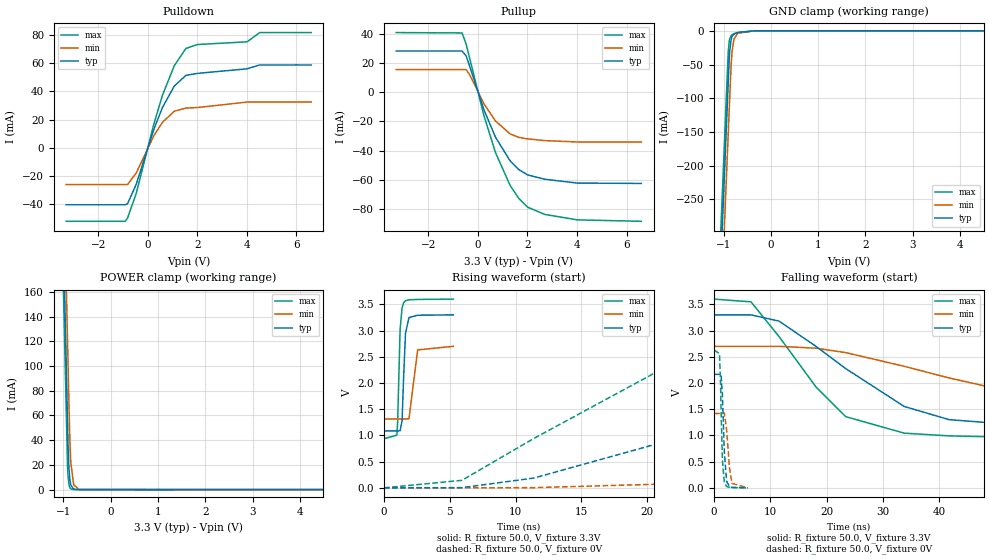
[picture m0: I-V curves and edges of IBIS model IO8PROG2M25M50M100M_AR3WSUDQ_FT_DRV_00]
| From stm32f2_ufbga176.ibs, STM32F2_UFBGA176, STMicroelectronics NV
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| *** New cell (Generated with 5.14beta1 (Sep 20 2010 13:23:23))
[Model]   IO8PROG2M25M50M100M_AR3WSUDQ_FT_DRV_00
Model_type 3-state
Polarity   Non-Inverting
Enable   Active-Low
| CAP_THRESHOLD on pad IOV33 is "CMOS" :
| Rising=10.0% of vddio   Falling=90.0% of vddio
| C_comp min and max val. don't necessarily correlate with the min and max pvt
| but are the smallest and greatest pad capacitance found.
| var   typ   min   max
C_comp   2.51760pF  2.40375pF  2.66060pF
Vmeas = 1.65V   | Reference voltage for timing measurements
Cref  = 50.0pF   | Timing specification test load capacitance value
Rref  = 10.0MOhm   | Timing specification test load resistance value
Vref  = 1.65V   | Timing specification test load voltage
[Model Spec]
| variable   typ   min   max
[Temperature Range] 25.0 125.0 -40.0
| variable   typ   min   max
[Voltage Range] 3.3V 2.7V 3.6V
| variable   typ   min   max
[POWER Clamp Reference] 3.3V 2.7V 3.6V
| variable   typ   min   max
[GND Clamp Reference] 0V 0V 0V
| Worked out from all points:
|   slope of the pulldown table from 0 to 0.495 V, typ, clamps not added: 20 ohm
|   slope of the pullup table from 0 to 0.495 V, typ, clamps not added: 21.7 ohm
|   GND clamp passes 1 mA (typ) near -0.59 V on its own axis
|   POWER clamp passes 1 mA (typ) near -0.81 V on its own axis
|   rising waveform, R_fixture 50.0, V_fixture 3.3V: 20-80 % time 185ps typ, 224ps min, 174ps max; typ from 1.09 V to 3.3 V
|   falling waveform, R_fixture 50.0, V_fixture 3.3V: 20-80 % time 18.1ns typ, 35.5ns min, 11.7ns max; typ from 3.3 V to 1.09 V
|   rising waveform, R_fixture 50.0, V_fixture 0V: 20-80 % time 19.4ns typ, 43.9ns min, 10.8ns max; typ from 0 V to 2.17 V
|   falling waveform, R_fixture 50.0, V_fixture 0V: 20-80 % time 445ps typ, 629ps min, 359ps max; typ from 2.17 V to 0.001 V
[POWER Clamp]
-3.3V     4.117A     4.183A     4.076A
-1.09V    360mA      425.6mA    319.3mA
-1.05V    292mA      357.6mA    251.3mA
-1.01V    224mA      289.6mA    183.3mA
-910mV    53.96mA    119.6mA    18.43mA
-900mV    36.96mA    102.6mA    11.2mA
-880mV    16.97mA    68.61mA    4.141mA
-860mV    7.791mA    38.56mA    1.53mA
-840mV    3.577mA    21.53mA    565.5uA
-780mV    346.2uA    3.745mA    28.55uA
-660mV    3.242uA    113.2uA    73.21nA
6.6V      0A         0A         0A
[GND Clamp]
-3.3V     -4.156A    -4.231A    -4.108A
-1.06V    -347.5mA   -423.2mA   -300.1mA
-940mV    -143.5mA   -219.2mA   -96.09mA
-900mV    -75.54mA   -151.2mA   -30.39mA
-880mV    -41.78mA   -117.2mA   -15.62mA
-870mV    -30.28mA   -100.2mA   -12.04mA
-840mV    -13.1mA    -50.87mA   -7.186mA
-820mV    -8.54mA    -30.65mA   -5.881mA
-780mV    -4.86mA    -12.37mA   -4.416mA
-700mV    -2.552mA   -3.603mA   -2.454mA
-350mV    -11.93uA   -60.06uA   -2.46uA
6.6V      10.25nA    1.32uA     122.8pA
| variable   typ   min   max
[Pullup Reference] 3.3V 2.7V 3.6V
| variable   typ   min   max
[Pulldown Reference] 0V 0V 0V
[Pullup]
-3.3V     28.36mA    15.61mA    40.99mA
-640mV    28.36mA    15.61mA    40.72mA
-480mV    25.12mA    15.61mA    33.23mA
-350mV    18.69mA    12.65mA    24.51mA
240mV     -11.89mA   -7.822mA   -15.87mA
710mV     -30.8mA    -19.68mA   -41.36mA
1.3V      -47.02mA   -28.56mA   -63.9mA
1.65V     -53.05mA   -30.92mA   -72.82mA
2.01V     -56.71mA   -31.98mA   -78.86mA
2.7V      -59.67mA   -33.14mA   -83.8mA
4.01V     -62.27mA   -34.07mA   -87.53mA
6.6V      -62.54mA   -34.07mA   -88.51mA
[Pulldown]
-3.3V     -40.26mA   -25.94mA   -51.99mA
-910mV    -40.26mA   -25.94mA   -51.99mA
-820mV    -39.59mA   -25.94mA   -49.78mA
-470mV    -25.89mA   -17.87mA   -32.39mA
240mV     12.97mA    8.52mA     16.62mA
590mV     28.62mA    18.11mA    37.2mA
1.07V     43.85mA    26mA       58.31mA
1.54V     51.42mA    28.24mA    70.48mA
2.01V     52.82mA    28.63mA    73.27mA
4.01V     56.05mA    32.5mA     75.18mA
4.52V     58.79mA    32.5mA     81.73mA
6.6V      58.79mA    32.5mA     81.73mA
[Ramp]
dV/dt_r 1.29886V/19.41372ns 851.11157mV/43.87102ns 1.57727V/10.7781ns
dV/dt_f 1.3278V/18.13381ns 831.267mV/35.53476ns 1.59819V/11.73814ns
R_load = 50.0
| Removed startup time: 0s 0s 0s  .
| Removed end time: 5.264ns.
[Rising Waveform]
R_fixture   = 50.0
V_fixture   = 3.3V
V_fixture_min = 2.7V
V_fixture_max = 3.6V
0s        1.087V     1.314V     936.3mV
980ps     1.087V     1.314V     1.005V
1.04ns    1.086V     1.314V     1.255V
1.226ns   1.09V      1.314V     3.019V
1.378ns   1.278V     1.314V     3.436V
1.486ns   2.063V     1.314V     3.527V
1.636ns   2.946V     1.312V     3.569V
1.902ns   3.248V     1.319V     3.586V
2.56ns    3.292V     2.631V     3.593V
5.268ns   3.299V     2.699V     3.599V
| Removed startup time: 0s 0s 0s  .
| Removed end time: 250.2ns.
[Falling Waveform]
R_fixture   = 50.0
V_fixture   = 3.3V
V_fixture_min = 2.7V
V_fixture_max = 3.6V
0s        3.3V       2.7V       3.6V
6.56ns    3.3V       2.7V       3.548V
11.56ns   3.18V      2.7V       2.885V
18.16ns   2.696V     2.664V     1.919V
23.4ns    2.275V     2.58V      1.359V
33.8ns    1.553V     2.319V     1.044V
41.76ns   1.302V     2.097V     992mV
58.96ns   1.16V      1.684V     953.1mV
85.32ns   1.107V     1.443V     940mV
250.3ns   1.087V     1.315V     936.3mV
| Removed startup time: 0s 0s 0s  .
| Removed end time: 242.72ns.
[Rising Waveform]
R_fixture   = 50.0
V_fixture   = 0V
V_fixture_min = 0V
V_fixture_max = 0V
0s        8.518nV    394.5nV    5.764nV
5.92ns    3.855mV    -137.4uV   143.5mV
11.4ns    188mV      3.643mV    944.4mV
20.84ns   846.3mV    70.12mV    2.228V
31.12ns   1.546V     245.4mV    2.545V
38.12ns   1.868V     393.2mV    2.594V
48.88ns   2.05V      635.5mV    2.618V
72.4ns    2.143V     1.077V     2.628V
93.8ns    2.159V     1.284V     2.629V
242.8ns   2.165V     1.419V     2.629V
| Removed startup time: 0s 0s 0s  .
| Removed end time: 5.988ns.
[Falling Waveform]
R_fixture   = 50.0
V_fixture   = 0V
V_fixture_min = 0V
V_fixture_max = 0V
0s        2.165V     1.419V     2.629V
960ps     2.166V     1.419V     2.56V
1.14ns    2.172V     1.419V     2.046V
1.272ns   2.134V     1.418V     1.377V
1.484ns   1.754V     1.419V     524.3mV
1.822ns   693mV      1.428V     110.8mV
2.22ns    128.6mV    1.119V     28.35mV
2.734ns   24.13mV    386mV      10.84mV
3.182ns   9.881mV    87.57mV    7.349mV
5.992ns   1.124mV    1.064mV    1.02mV
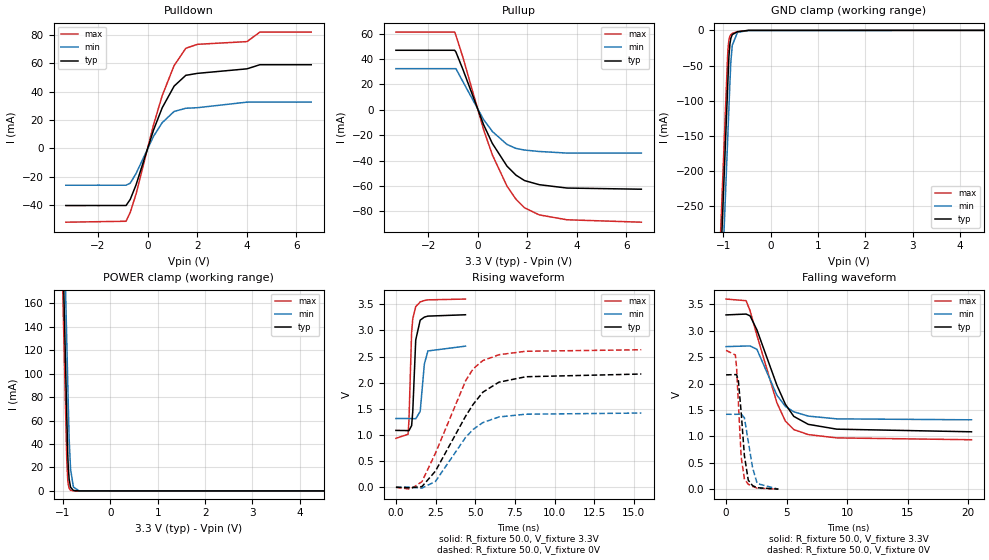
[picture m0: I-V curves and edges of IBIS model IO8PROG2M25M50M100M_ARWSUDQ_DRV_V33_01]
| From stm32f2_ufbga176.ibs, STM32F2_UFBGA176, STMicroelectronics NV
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| *** New cell (Generated with 5.14beta1 (Sep 20 2010 13:23:23))
[Model]   IO8PROG2M25M50M100M_ARWSUDQ_DRV_V33_01
Model_type 3-state
Polarity   Non-Inverting
Enable   Active-Low
| CAP_THRESHOLD on pad IOV33 is "CMOS" :
| Rising=10.0% of vddio   Falling=90.0% of vddio
| C_comp min and max val. don't necessarily correlate with the min and max pvt
| but are the smallest and greatest pad capacitance found.
| var   typ   min   max
C_comp   2.45675pF  2.35635pF  2.58870pF
Vmeas = 1.65V   | Reference voltage for timing measurements
Cref  = 50.0pF   | Timing specification test load capacitance value
Rref  = 1.0MOhm   | Timing specification test load resistance value
Vref  = 1.65V   | Timing specification test load voltage
[Model Spec]
| variable   typ   min   max
[Temperature Range] 25.0 125.0 -40.0
| variable   typ   min   max
[Voltage Range] 3.3V 2.7V 3.6V
| variable   typ   min   max
[POWER Clamp Reference] 3.3V 2.7V 3.6V
| variable   typ   min   max
[GND Clamp Reference] 0V 0V 0V
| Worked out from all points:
|   slope of the pulldown table from 0 to 0.495 V, typ, clamps not added: 20 ohm
|   slope of the pullup table from 0 to 0.495 V, typ, clamps not added: 21.7 ohm
|   GND clamp passes 1 mA (typ) near -0.62 V on its own axis
|   POWER clamp passes 1 mA (typ) near -0.81 V on its own axis
|   rising waveform, R_fixture 50.0, V_fixture 3.3V: 20-80 % time 186ps typ, 233ps min, 172ps max; typ from 1.09 V to 3.3 V
|   falling waveform, R_fixture 50.0, V_fixture 3.3V: 20-80 % time 2.28ns typ, 1.79ns min, 2.12ns max; typ from 3.3 V to 1.09 V
|   rising waveform, R_fixture 50.0, V_fixture 0V: 20-80 % time 2.5ns typ, 2.07ns min, 2.19ns max; typ from 0 V to 2.17 V
|   falling waveform, R_fixture 50.0, V_fixture 0V: 20-80 % time 440ps typ, 624ps min, 354ps max; typ from 2.17 V to 0.001 V
[POWER Clamp]
-3.3V     4.11A      4.173A     4.072A
-1.09V    352.6mA    415.9mA    314.7mA
-1.05V    284.6mA    347.9mA    246.7mA
-1.01V    216.6mA    279.9mA    178.7mA
-920mV    63.6mA     126.9mA    25.98mA
-900mV    31.61mA    92.95mA    9.679mA
-890mV    21.44mA    75.95mA    5.93mA
-870mV    9.888mA    44.06mA    2.262mA
-840mV    3.126mA    18.4mA     586.7uA
-780mV    356.4uA    3.233mA    107.9uA
-660mV    37.87uA    120.8uA    47.09uA
6.6V      0A         0A         0A
[GND Clamp]
-3.3V     -4.149A    -4.224A    -4.103A
-1.06V    -340.8mA   -415.7mA   -294.7mA
-940mV    -136.8mA   -211.7mA   -90.7mA
-910mV    -85.75mA   -160.7mA   -39.7mA
-900mV    -68.75mA   -143.7mA   -26.69mA
-880mV    -36.92mA   -109.7mA   -13.58mA
-860mV    -19.7mA    -75.66mA   -8.314mA
-840mV    -11.43mA   -45.13mA   -6.003mA
-810mV    -6.09mA    -21.34mA   -4.418mA
-700mV    -1.961mA   -2.954mA   -1.882mA
-470mV    -105.5uA   -264uA     -47.31uA
6.6V      9.775nA    1.217uA    66.58pA
| variable   typ   min   max
[Pullup Reference] 3.3V 2.7V 3.6V
| variable   typ   min   max
[Pulldown Reference] 0V 0V 0V
[Pullup]
-3.3V     46.87mA    32.39mA    61.2mA
-930mV    46.87mA    32.39mA    61.2mA
-880mV    45.52mA    32.39mA    58.63mA
-590mV    31.39mA    21.86mA    40.83mA
240mV     -11.89mA   -7.822mA   -15.87mA
590mV     -26.5mA    -17.07mA   -35.52mA
1.18V     -44.36mA   -27.27mA   -60.11mA
1.54V     -51.43mA   -30.39mA   -70.35mA
1.89V     -55.75mA   -31.69mA   -77.18mA
2.48V     -58.98mA   -32.83mA   -82.75mA
3.6V      -61.62mA   -34.07mA   -86.61mA
6.6V      -62.54mA   -34.07mA   -88.51mA
[Pulldown]
-3.3V     -40.26mA   -25.94mA   -51.99mA
-870mV    -40.25mA   -25.94mA   -51.33mA
-700mV    -35.92mA   -24.51mA   -45.06mA
-470mV    -25.89mA   -17.87mA   -32.39mA
240mV     12.97mA    8.52mA     16.62mA
590mV     28.62mA    18.11mA    37.2mA
1.07V     43.85mA    26mA       58.31mA
1.54V     51.42mA    28.24mA    70.48mA
2.01V     52.82mA    28.63mA    73.27mA
4.01V     56.01mA    32.56mA    75.18mA
4.53V     58.9mA     32.56mA    81.88mA
6.6V      58.9mA     32.56mA    81.88mA
[Ramp]
dV/dt_r 1.29886V/2.49642ns 851.30661mV/2.06906ns 1.57728V/2.19388ns
dV/dt_f 1.32782V/2.28321ns 831.60245mV/1.78812ns 1.59819V/2.1203ns
R_load = 50.0
| Removed startup time: 0s 0s 0s  .
| Removed end time: 4.382ns.
[Rising Waveform]
R_fixture   = 50.0
V_fixture   = 3.3V
V_fixture_min = 2.7V
V_fixture_max = 3.6V
0s        1.087V     1.314V     936.3mV
764ps     1.084V     1.314V     1.013V
821ps     1.083V     1.314V     1.272V
989ps     1.178V     1.313V     2.957V
1.061ns   1.445V     1.313V     3.219V
1.248ns   2.816V     1.309V     3.453V
1.53ns    3.195V     1.451V     3.543V
1.792ns   3.253V     2.356V     3.57V
2.014ns   3.272V     2.606V     3.583V
4.384ns   3.298V     2.698V     3.598V
| Removed startup time: 0s 0s 0s  .
| Removed end time: 20.27ns.
[Falling Waveform]
R_fixture   = 50.0
V_fixture   = 3.3V
V_fixture_min = 2.7V
V_fixture_max = 3.6V
0s        3.3V       2.7V       3.6V
1.655ns   3.316V     2.711V     3.569V
1.985ns   3.282V     2.711V     3.38V
2.55ns    3.017V     2.649V     2.914V
4.195ns   1.972V     1.782V     1.64V
4.9ns     1.609V     1.568V     1.289V
5.595ns   1.379V     1.466V     1.129V
6.795ns   1.228V     1.384V     1.034V
9.15ns    1.137V     1.332V     971.7mV
20.28ns   1.087V     1.314V     936.6mV
| Removed startup time: 0s 0s 0s  .
| Removed end time: 15.46ns.
[Rising Waveform]
R_fixture   = 50.0
V_fixture   = 0V
V_fixture_min = 0V
V_fixture_max = 0V
0s        11.88nV    319.5nV    8.559nV
920ps     -7.716mV   80.7uV     -36.12mV
1.64ns    13.22mV    -14.92mV   107.4mV
2.49ns    308.8mV    111.2mV    650.3mV
4.395ns   1.361V     955.3mV    2.037V
4.875ns   1.588V     1.108V     2.267V
5.48ns    1.818V     1.237V     2.422V
6.49ns    2.009V     1.344V     2.534V
8.185ns   2.113V     1.397V     2.6V
15.47ns   2.165V     1.419V     2.629V
| Removed startup time: 0s 0s 0s  .
| Removed end time: 4.313ns.
[Falling Waveform]
R_fixture   = 50.0
V_fixture   = 0V
V_fixture_min = 0V
V_fixture_max = 0V
0s        2.165V     1.419V     2.629V
771ps     2.17V      1.418V     2.542V
874ps     2.166V     1.418V     2.289V
1.017ns   2.057V     1.42V      1.644V
1.248ns   1.462V     1.426V     612.2mV
1.516ns   635.4mV    1.352V     195.7mV
1.838ns   170mV      900.3mV    93.88mV
2.192ns   67.61mV    408.4mV    52.69mV
2.574ns   28.63mV    107.1mV    19.97mV
4.315ns   1.209mV    1.558mV    835.1uV
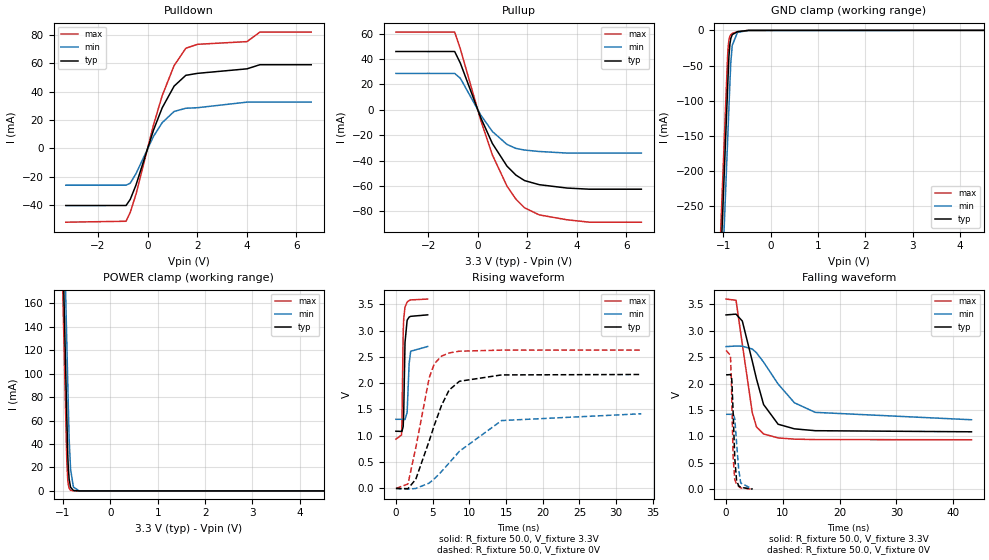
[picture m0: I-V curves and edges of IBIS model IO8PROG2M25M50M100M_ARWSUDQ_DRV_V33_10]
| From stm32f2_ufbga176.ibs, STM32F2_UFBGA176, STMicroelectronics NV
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| *** New cell (Generated with 5.14beta1 (Sep 20 2010 13:23:23))
[Model]   IO8PROG2M25M50M100M_ARWSUDQ_DRV_V33_10
Model_type 3-state
Polarity   Non-Inverting
Enable   Active-Low
| CAP_THRESHOLD on pad IOV33 is "CMOS" :
| Rising=10.0% of vddio   Falling=90.0% of vddio
| C_comp min and max val. don't necessarily correlate with the min and max pvt
| but are the smallest and greatest pad capacitance found.
| var   typ   min   max
C_comp   2.45675pF  2.35635pF  2.58870pF
Vmeas = 1.65V   | Reference voltage for timing measurements
Cref  = 50.0pF   | Timing specification test load capacitance value
Rref  = 1.0MOhm   | Timing specification test load resistance value
Vref  = 1.65V   | Timing specification test load voltage
[Model Spec]
| variable   typ   min   max
[Temperature Range] 25.0 125.0 -40.0
| variable   typ   min   max
[Voltage Range] 3.3V 2.7V 3.6V
| variable   typ   min   max
[POWER Clamp Reference] 3.3V 2.7V 3.6V
| variable   typ   min   max
[GND Clamp Reference] 0V 0V 0V
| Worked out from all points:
|   slope of the pulldown table from 0 to 0.495 V, typ, clamps not added: 20 ohm
|   slope of the pullup table from 0 to 0.495 V, typ, clamps not added: 21.7 ohm
|   GND clamp passes 1 mA (typ) near -0.62 V on its own axis
|   POWER clamp passes 1 mA (typ) near -0.81 V on its own axis
|   rising waveform, R_fixture 50.0, V_fixture 3.3V: 20-80 % time 186ps typ, 231ps min, 172ps max; typ from 1.09 V to 3.3 V
|   falling waveform, R_fixture 50.0, V_fixture 3.3V: 20-80 % time 3.17ns typ, 6.13ns min, 2.08ns max; typ from 3.3 V to 1.09 V
|   rising waveform, R_fixture 50.0, V_fixture 0V: 20-80 % time 3.27ns typ, 6.06ns min, 2.16ns max; typ from 0 V to 2.17 V
|   falling waveform, R_fixture 50.0, V_fixture 0V: 20-80 % time 440ps typ, 624ps min, 354ps max; typ from 2.17 V to 0.001 V
[POWER Clamp]
-3.3V     4.11A      4.173A     4.072A
-1.09V    352.6mA    415.9mA    314.7mA
-1.05V    284.6mA    347.9mA    246.7mA
-1.01V    216.6mA    279.9mA    178.7mA
-920mV    63.6mA     126.9mA    25.98mA
-900mV    31.61mA    92.95mA    9.679mA
-890mV    21.44mA    75.95mA    5.93mA
-870mV    9.888mA    44.06mA    2.262mA
-840mV    3.126mA    18.4mA     586.7uA
-780mV    356.4uA    3.233mA    107.9uA
-660mV    37.87uA    120.8uA    47.09uA
6.6V      0A         0A         0A
[GND Clamp]
-3.3V     -4.149A    -4.224A    -4.103A
-1.06V    -340.8mA   -415.7mA   -294.7mA
-940mV    -136.8mA   -211.7mA   -90.7mA
-910mV    -85.75mA   -160.7mA   -39.7mA
-900mV    -68.75mA   -143.7mA   -26.69mA
-880mV    -36.92mA   -109.7mA   -13.58mA
-860mV    -19.7mA    -75.66mA   -8.314mA
-840mV    -11.43mA   -45.13mA   -6.003mA
-810mV    -6.09mA    -21.34mA   -4.418mA
-700mV    -1.961mA   -2.954mA   -1.882mA
-470mV    -105.5uA   -264uA     -47.31uA
6.6V      9.775nA    1.217uA    66.58pA
| variable   typ   min   max
[Pullup Reference] 3.3V 2.7V 3.6V
| variable   typ   min   max
[Pulldown Reference] 0V 0V 0V
[Pullup]
-3.3V     45.89mA    28.66mA    61.2mA
-930mV    45.89mA    28.66mA    61.2mA
-700mV    36.7mA     24.8mA     47.91mA
120mV     -6.142mA   -4.065mA   -8.189mA
590mV     -26.5mA    -17.07mA   -35.52mA
1.18V     -44.36mA   -27.27mA   -60.11mA
1.54V     -51.43mA   -30.39mA   -70.35mA
1.89V     -55.75mA   -31.69mA   -77.18mA
2.48V     -58.98mA   -32.83mA   -82.75mA
3.6V      -61.62mA   -34.07mA   -86.61mA
4.51V     -62.54mA   -34.07mA   -88.51mA
6.6V      -62.54mA   -34.07mA   -88.51mA
[Pulldown]
-3.3V     -40.26mA   -25.94mA   -51.99mA
-870mV    -40.25mA   -25.94mA   -51.33mA
-700mV    -35.92mA   -24.51mA   -45.06mA
-470mV    -25.89mA   -17.87mA   -32.39mA
240mV     12.97mA    8.52mA     16.62mA
590mV     28.62mA    18.11mA    37.2mA
1.07V     43.85mA    26mA       58.31mA
1.54V     51.42mA    28.24mA    70.48mA
2.01V     52.82mA    28.63mA    73.27mA
4.01V     56.01mA    32.56mA    75.18mA
4.53V     58.9mA     32.56mA    81.88mA
6.6V      58.9mA     32.56mA    81.88mA
[Ramp]
dV/dt_r 1.29886V/3.26621ns 851.30598mV/6.05634ns 1.57728V/2.1635ns
dV/dt_f 1.32782V/3.17182ns 831.60151mV/6.14241ns 1.59819V/2.07975ns
R_load = 50.0
| Removed startup time: 0s 0s 0s  .
| Removed end time: 4.325ns.
[Rising Waveform]
R_fixture   = 50.0
V_fixture   = 3.3V
V_fixture_min = 2.7V
V_fixture_max = 3.6V
0s        1.087V     1.314V     936.3mV
765ps     1.084V     1.314V     1.015V
822ps     1.083V     1.314V     1.28V
990ps     1.179V     1.313V     2.962V
1.063ns   1.456V     1.313V     3.223V
1.237ns   2.773V     1.309V     3.446V
1.529ns   3.196V     1.448V     3.542V
1.798ns   3.255V     2.371V     3.569V
2.011ns   3.27V      2.607V     3.582V
4.327ns   3.298V     2.697V     3.598V
| Removed startup time: 0s 0s 0s  .
| Removed end time: 43.185ns.
[Falling Waveform]
R_fixture   = 50.0
V_fixture   = 3.3V
V_fixture_min = 2.7V
V_fixture_max = 3.6V
0s        3.3V       2.7V       3.6V
1.755ns   3.315V     2.711V     3.577V
2.865ns   3.183V     2.707V     2.746V
4.615ns   2.425V     2.655V     1.45V
5.365ns   2.084V     2.582V     1.178V
6.605ns   1.604V     2.407V     1.046V
9.165ns   1.23V      1.991V     971.1mV
12.04ns   1.143V     1.636V     948mV
15.7ns    1.108V     1.455V     939.8mV
43.2ns    1.087V     1.315V     936.3mV
| Removed startup time: 0s 0s 0s  .
| Removed end time: 33.425ns.
[Rising Waveform]
R_fixture   = 50.0
V_fixture   = 0V
V_fixture_min = 0V
V_fixture_max = 0V
0s        11.86nV    319.5nV    8.555nV
1.64ns    -3.854mV   -13.59mV   84.41mV
2.705ns   174.4mV    149.5uV    772.3mV
4.535ns   903.2mV    102.6mV    2.103V
5.235ns   1.203V     184.4mV    2.37V
6.205ns   1.575V     320.7mV    2.513V
7.245ns   1.869V     482.8mV    2.574V
8.65ns    2.036V     706.4mV    2.608V
14.4ns    2.157V     1.29V      2.628V
33.44ns   2.165V     1.419V     2.629V
| Removed startup time: 0s 0s 0s  .
| Removed end time: 4.662ns.
[Falling Waveform]
R_fixture   = 50.0
V_fixture   = 0V
V_fixture_min = 0V
V_fixture_max = 0V
0s        2.165V     1.419V     2.629V
777ps     2.17V      1.418V     2.533V
937ps     2.142V     1.419V     2.055V
1.023ns   2.049V     1.42V      1.612V
1.255ns   1.438V     1.427V     590.5mV
1.537ns   585.5mV    1.336V     183.7mV
1.859ns   157.8mV    869.2mV    90.57mV
2.233ns   62.07mV    367.7mV    52.03mV
2.586ns   35.32mV    116.1mV    23.67mV
4.664ns   1.466mV    3.442mV    862.7uV
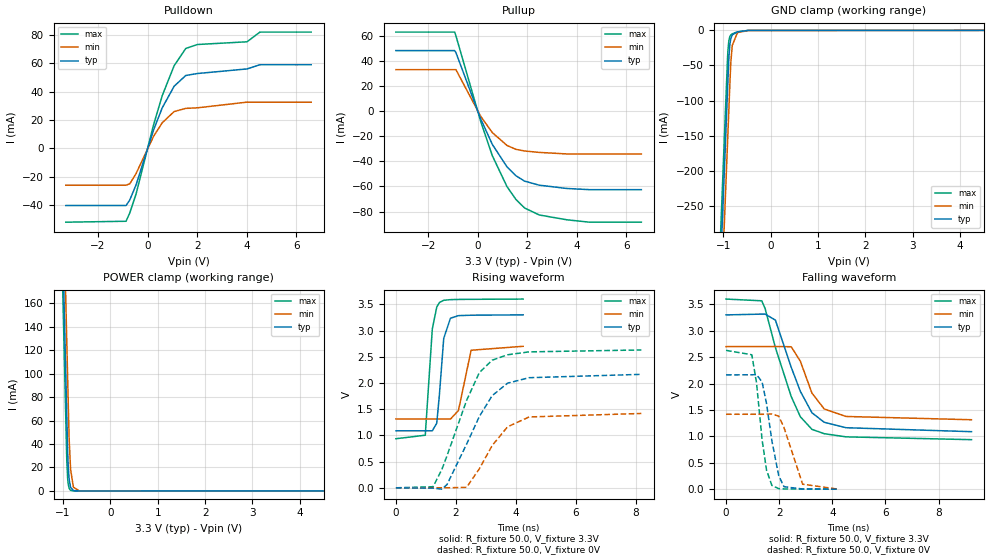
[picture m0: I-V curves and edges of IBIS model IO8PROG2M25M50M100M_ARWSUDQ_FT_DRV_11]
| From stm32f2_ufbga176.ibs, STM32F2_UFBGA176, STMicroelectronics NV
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| *** New cell (Generated with 5.14beta1 (Sep 20 2010 13:23:23))
[Model]   IO8PROG2M25M50M100M_ARWSUDQ_FT_DRV_11
Model_type 3-state
Polarity   Non-Inverting
Enable   Active-Low
| CAP_THRESHOLD on pad IOV33 is "CMOS" :
| Rising=10.0% of vddio   Falling=90.0% of vddio
| C_comp min and max val. don't necessarily correlate with the min and max pvt
| but are the smallest and greatest pad capacitance found.
| var   typ   min   max
C_comp   2.32810pF  2.21815pF  2.46460pF
Vmeas = 1.65V   | Reference voltage for timing measurements
Cref  = 50.0pF   | Timing specification test load capacitance value
Rref  = 10.0MOhm   | Timing specification test load resistance value
Vref  = 1.65V   | Timing specification test load voltage
[Model Spec]
| variable   typ   min   max
[Temperature Range] 25.0 125.0 -40.0
| variable   typ   min   max
[Voltage Range] 3.3V 2.7V 3.6V
| variable   typ   min   max
[POWER Clamp Reference] 3.3V 2.7V 3.6V
| variable   typ   min   max
[GND Clamp Reference] 0V 0V 0V
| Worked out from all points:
|   slope of the pulldown table from 0 to 0.495 V, typ, clamps not added: 20 ohm
|   slope of the pullup table from 0 to 0.495 V, typ, clamps not added: 21.7 ohm
|   GND clamp passes 1 mA (typ) near -0.61 V on its own axis
|   POWER clamp passes 1 mA (typ) near -0.81 V on its own axis
|   rising waveform, R_fixture 50.0, V_fixture 3.3V: 20-80 % time 176ps typ, 219ps min, 161ps max; typ from 1.09 V to 3.3 V
|   falling waveform, R_fixture 50.0, V_fixture 3.3V: 20-80 % time 1.02ns typ, 727ps min, 1.04ns max; typ from 3.3 V to 1.09 V
|   rising waveform, R_fixture 50.0, V_fixture 0V: 20-80 % time 1.12ns typ, 958ps min, 1.04ns max; typ from 0 V to 2.16 V
|   falling waveform, R_fixture 50.0, V_fixture 0V: 20-80 % time 408ps typ, 480ps min, 340ps max; typ from 2.17 V to 0.001 V
[POWER Clamp]
-3.3V     4.11A      4.173A     4.072A
-1.09V    352.5mA    415.9mA    314.5mA
-1.05V    284.5mA    347.9mA    246.5mA
-1.01V    216.5mA    279.9mA    178.5mA
-920mV    63.51mA    126.9mA    25.85mA
-900mV    31.51mA    92.9mA     9.552mA
-890mV    21.35mA    75.9mA     5.807mA
-870mV    9.804mA    44.01mA    2.146mA
-840mV    3.05mA     18.36mA    482.1uA
-780mV    295.2uA    3.194mA    24.34uA
-660mV    2.764uA    96.52uA    62.42nA
6.6V      0A         0A         0A
[GND Clamp]
-3.3V     -4.149A    -4.224A    -4.103A
-1.06V    -341mA     -415.8mA   -295.1mA
-940mV    -137mA     -211.8mA   -91.11mA
-910mV    -86.01mA   -160.8mA   -40.11mA
-900mV    -69.01mA   -143.8mA   -27.13mA
-880mV    -37.2mA    -109.8mA   -14.07mA
-860mV    -20.02mA   -75.82mA   -8.837mA
-840mV    -11.77mA   -45.3mA    -6.542mA
-810mV    -6.468mA   -21.54mA   -4.94mA
-700mV    -2.247mA   -3.206mA   -2.168mA
-470mV    -130uA     -313.8uA   -60.76uA
6.6V      10.47nA    1.304uA    84.25pA
| variable   typ   min   max
[Pullup Reference] 3.3V 2.7V 3.6V
| variable   typ   min   max
[Pulldown Reference] 0V 0V 0V
[Pullup]
-3.3V     48.39mA    33.18mA    63.15mA
-930mV    48.39mA    33.18mA    63.15mA
-880mV    46.82mA    33.18mA    60.2mA
120mV     -6.142mA   -4.065mA   -8.189mA
590mV     -26.5mA    -17.07mA   -35.52mA
1.18V     -44.36mA   -27.27mA   -60.11mA
1.54V     -51.43mA   -30.39mA   -70.35mA
1.89V     -55.75mA   -31.69mA   -77.18mA
2.48V     -58.98mA   -32.83mA   -82.75mA
3.6V      -61.62mA   -34.07mA   -86.61mA
4.51V     -62.54mA   -34.07mA   -88.51mA
6.6V      -62.54mA   -34.07mA   -88.51mA
[Pulldown]
-3.3V     -40.26mA   -25.94mA   -51.99mA
-870mV    -40.25mA   -25.94mA   -51.33mA
-720mV    -36.35mA   -24.93mA   -45.5mA
-470mV    -25.89mA   -17.87mA   -32.39mA
240mV     12.97mA    8.52mA     16.62mA
590mV     28.62mA    18.11mA    37.2mA
1.07V     43.85mA    26mA       58.31mA
1.54V     51.42mA    28.24mA    70.48mA
2.01V     52.82mA    28.63mA    73.27mA
4.01V     56.05mA    32.64mA    75.18mA
4.53V     59mA       32.64mA    82.02mA
6.6V      59mA       32.64mA    82.02mA
[Ramp]
dV/dt_r 1.29893V/1.1191ns 851.30678mV/959.17345ps 1.57728V/1.0392ns
dV/dt_f 1.32782V/1.0212ns 831.60268mV/728.00495ps 1.59819V/1.04332ns
R_load = 50.0
| Removed startup time: 0s 0s 0s  .
| Removed end time: 4.244ns.
[Rising Waveform]
R_fixture   = 50.0
V_fixture   = 3.3V
V_fixture_min = 2.7V
V_fixture_max = 3.6V
0s        1.087V     1.314V     936.3mV
979ps     1.087V     1.314V     1.003V
1.214ns   1.087V     1.314V     3.029V
1.362ns   1.233V     1.314V     3.447V
1.449ns   1.761V     1.314V     3.533V
1.595ns   2.851V     1.313V     3.577V
1.819ns   3.234V     1.31V      3.589V
2.086ns   3.284V     1.474V     3.593V
2.509ns   3.292V     2.624V     3.595V
4.246ns   3.299V     2.699V     3.6V
| Removed startup time: 0s 0s 0s  .
| Removed end time: 9.234ns.
[Falling Waveform]
R_fixture   = 50.0
V_fixture   = 3.3V
V_fixture_min = 2.7V
V_fixture_max = 3.6V
0s        3.3V       2.7V       3.6V
1.343ns   3.315V     2.7V       3.567V
1.468ns   3.316V     2.7V       3.425V
1.858ns   3.201V     2.702V     2.68V
2.452ns   2.309V     2.697V     1.755V
2.796ns   1.853V     2.423V     1.372V
3.232ns   1.447V     1.82V      1.133V
3.694ns   1.267V     1.519V     1.051V
4.514ns   1.164V     1.377V     990.9mV
9.236ns   1.089V     1.315V     937.8mV
| Removed startup time: 0s 0s 0s  .
| Removed end time: 8.187ns.
[Rising Waveform]
R_fixture   = 50.0
V_fixture   = 0V
V_fixture_min = 0V
V_fixture_max = 0V
0s        8.056nV    322.2nV    5.733nV
1.24ns    -6.525mV   5.549uV    20.89mV
1.53ns    -25.98mV   120.3uV    345.7mV
1.705ns   61.84mV    276.5uV    613.1mV
2.358ns   832.9mV    9.717mV    1.667V
2.781ns   1.357V     360.3mV    2.195V
3.211ns   1.758V     805.6mV    2.434V
3.723ns   1.995V     1.163V     2.537V
4.444ns   2.1V       1.351V     2.593V
8.189ns   2.164V     1.418V     2.629V
| Removed startup time: 0s 0s 0s  .
| Removed end time: 4.217ns.
[Falling Waveform]
R_fixture   = 50.0
V_fixture   = 0V
V_fixture_min = 0V
V_fixture_max = 0V
0s        2.165V     1.419V     2.629V
969ps     2.166V     1.419V     2.545V
1.147ns   2.17V      1.419V     2.014V
1.357ns   2.029V     1.418V     933.2mV
1.523ns   1.623V     1.42V      361.6mV
1.726ns   914.9mV    1.424V     70.03mV
1.982ns   254.3mV    1.383V     10.46mV
2.182ns   46.74mV    1.166V     5.079mV
2.882ns   3.496mV    94.51mV    2.029mV
4.219ns   693.3uV    845.4uV    501.4uV
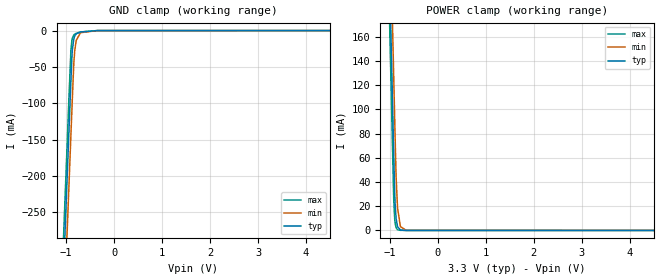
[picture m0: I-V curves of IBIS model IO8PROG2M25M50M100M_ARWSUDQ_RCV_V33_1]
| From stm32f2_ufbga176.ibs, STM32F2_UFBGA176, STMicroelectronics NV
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| *** New cell (Generated with 5.14beta1 (Sep 20 2010 13:23:23))
[Model]   IO8PROG2M25M50M100M_ARWSUDQ_RCV_V33_1
Model_type Input
Polarity   Non-Inverting
Enable   Active-Low
| CAP_THRESHOLD on pad IOV33 is "CMOS" :
| Rising=10.0% of vddio   Falling=90.0% of vddio
| C_comp min and max val. don't necessarily correlate with the min and max pvt
| but are the smallest and greatest pad capacitance found.
| var   typ   min   max
C_comp   2.45410pF  2.36075pF  2.57700pF
Vinl = 810.0mV | Dummy value overriden by next lines
Vinh = 2.52V | Dummy value overriden by next lines
[Model Spec]
| TIME_THRESHOLD on pin ZIV33 is "CORE" :
| Rising=40.0% of vddio   Falling=60.0% of vddio
Vinl 1.48450V 1.23350V 1.61250V
Vinh 1.48450V 1.23350V 1.61250V
| variable   typ   min   max
[Temperature Range] 25.0 125.0 -40.0
| variable   typ   min   max
[Voltage Range] 3.3V 2.7V 3.6V
| variable   typ   min   max
[POWER Clamp Reference] 3.3V 2.7V 3.6V
| variable   typ   min   max
[GND Clamp Reference] 0V 0V 0V
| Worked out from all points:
|   GND clamp passes 1 mA (typ) near -0.62 V on its own axis
|   POWER clamp passes 1 mA (typ) near -0.81 V on its own axis
[POWER Clamp]
-3.3V     4.11A      4.173A     4.072A
-1.09V    352.6mA    415.9mA    314.7mA
-1.05V    284.6mA    347.9mA    246.7mA
-1.01V    216.6mA    279.9mA    178.7mA
-920mV    63.6mA     126.9mA    25.98mA
-900mV    31.61mA    92.95mA    9.679mA
-890mV    21.44mA    75.95mA    5.93mA
-870mV    9.888mA    44.06mA    2.262mA
-840mV    3.126mA    18.4mA     586.7uA
-780mV    356.4uA    3.233mA    107.9uA
-660mV    37.87uA    120.8uA    47.09uA
6.6V      0A         0A         0A
[GND Clamp]
-3.3V     -4.149A    -4.224A    -4.103A
-1.06V    -340.8mA   -415.7mA   -294.7mA
-940mV    -136.8mA   -211.7mA   -90.7mA
-900mV    -68.75mA   -143.7mA   -26.69mA
-880mV    -36.92mA   -109.7mA   -13.58mA
-870mV    -26.73mA   -92.66mA   -10.38mA
-840mV    -11.43mA   -45.13mA   -6.003mA
-820mV    -7.322mA   -27.2mA    -4.821mA
-790mV    -4.504mA   -13.49mA   -3.791mA
-700mV    -1.961mA   -2.954mA   -1.882mA
-350mV    -6.427uA   -36.3uA    -1.194uA
6.6V      9.775nA    1.217uA    66.57pA
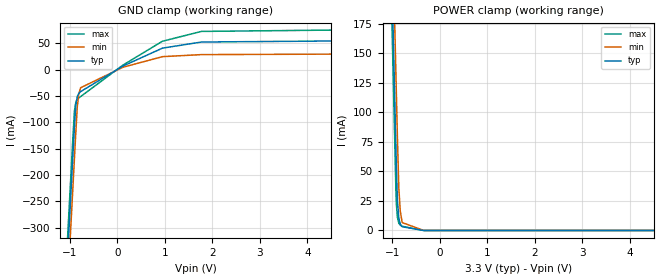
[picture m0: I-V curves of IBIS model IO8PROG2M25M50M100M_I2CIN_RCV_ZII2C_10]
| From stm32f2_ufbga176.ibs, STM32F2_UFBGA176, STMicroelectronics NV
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| *** New cell (Generated with 5.14beta1 (Sep 20 2010 13:23:23))
[Model]   IO8PROG2M25M50M100M_I2CIN_RCV_ZII2C_10
Model_type Input
Polarity   Non-Inverting
Enable   Active-Low
| CAP_THRESHOLD on pad IOV33 is "CMOS" :
| Rising=10.0% of vddio   Falling=90.0% of vddio
| C_comp min and max val. don't necessarily correlate with the min and max pvt
| but are the smallest and greatest pad capacitance found.
| var   typ   min   max
C_comp   2.13950pF  2.03575pF  2.25660pF
Vinl = 810.0mV | Dummy value overriden by next lines
Vinh = 2.52V | Dummy value overriden by next lines
[Model Spec]
| TIME_THRESHOLD on pin ZII2CV12 is "CORE" :
| Rising=40.0% of vdd   Falling=60.0% of vdd
Vinl 1.25450V 1.03850V 1.36250V
Vinh 1.66150V 1.36950V 1.82450V
| variable   typ   min   max
[Temperature Range] 25.0 125.0 -40.0
| variable   typ   min   max
[Voltage Range] 3.3V 2.7V 3.6V
| variable   typ   min   max
[POWER Clamp Reference] 3.3V 2.7V 3.6V
| variable   typ   min   max
[GND Clamp Reference] 0V 0V 0V
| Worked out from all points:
|   GND clamp passes 1 mA (typ) near -0.02 V on its own axis
|   POWER clamp passes 1 mA (typ) near -0.62 V on its own axis
[POWER Clamp]
-3.3V     4.113A     4.176A     4.076A
-1.09V    357mA      419.2mA    320.8mA
-1.05V    289mA      351.2mA    252.8mA
-1.01V    221mA      283.2mA    184.9mA
-920mV    68.07mA    130.3mA    32.01mA
-910mV    51.08mA    113.3mA    21.64mA
-890mV    25.6mA     79.28mA    11.28mA
-860mV    10.4mA     36.05mA    6.133mA
-830mV    5.371mA    16.57mA    4.527mA
-790mV    3.177mA    6.724mA    3.572mA
-340mV    0A         46uA       21uA
6.6V      0A         0A         0A
[GND Clamp]
-3.3V     -4.189A    -4.249A    -4.155A
-1.06V    -380.8mA   -441.1mA   -346.5mA
-940mV    -176.8mA   -237.1mA   -142.5mA
-900mV    -108.8mA   -169.1mA   -78.46mA
-870mV    -66.81mA   -118.1mA   -61.62mA
-840mV    -51.26mA   -70.71mA   -56.41mA
-810mV    -45.36mA   -47.08mA   -53.83mA
-770mV    -41.78mA   -34.45mA   -51.23mA
120mV     6.714mA    4.461mA    8.567mA
950mV     40.72mA    24.58mA    53.81mA
1.77V     52.39mA    28.47mA    72.51mA
6.6V      55.76mA    30.09mA    76.94mA
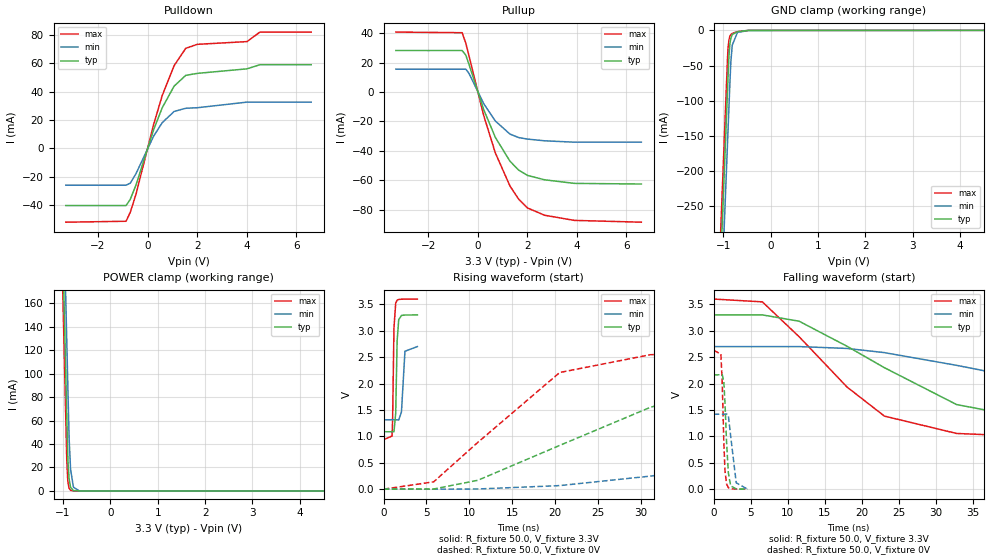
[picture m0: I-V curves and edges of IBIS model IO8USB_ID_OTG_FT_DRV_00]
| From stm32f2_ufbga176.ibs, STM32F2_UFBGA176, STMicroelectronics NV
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| *** New cell (Generated with 5.14beta1 (Sep 20 2010 13:23:23))
[Model]   IO8USB_ID_OTG_FT_DRV_00
Model_type 3-state
Polarity   Non-Inverting
Enable   Active-Low
| CAP_THRESHOLD on pad IOV33 is "CMOS" :
| Rising=10.0% of vddio   Falling=90.0% of vddio
| C_comp min and max val. don't necessarily correlate with the min and max pvt
| but are the smallest and greatest pad capacitance found.
| var   typ   min   max
C_comp   2.14880pF  2.04280pF  2.27520pF
Vmeas = 1.65V   | Reference voltage for timing measurements
Cref  = 50.0pF   | Timing specification test load capacitance value
Rref  = 10.0MOhm   | Timing specification test load resistance value
Vref  = 1.65V   | Timing specification test load voltage
[Model Spec]
| variable   typ   min   max
[Temperature Range] 25.0 125.0 -40.0
| variable   typ   min   max
[Voltage Range] 3.3V 2.7V 3.6V
| variable   typ   min   max
[POWER Clamp Reference] 3.3V 2.7V 3.6V
| variable   typ   min   max
[GND Clamp Reference] 0V 0V 0V
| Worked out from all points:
|   slope of the pulldown table from 0 to 0.495 V, typ, clamps not added: 20 ohm
|   slope of the pullup table from 0 to 0.495 V, typ, clamps not added: 21.7 ohm
|   GND clamp passes 1 mA (typ) near -0.62 V on its own axis
|   POWER clamp passes 1 mA (typ) near -0.81 V on its own axis
|   rising waveform, R_fixture 50.0, V_fixture 3.3V: 20-80 % time 162ps typ, 212ps min, 146ps max; typ from 1.09 V to 3.3 V
|   falling waveform, R_fixture 50.0, V_fixture 3.3V: 20-80 % time 18.1ns typ, 35.4ns min, 11.7ns max; typ from 3.3 V to 1.09 V
|   rising waveform, R_fixture 50.0, V_fixture 0V: 20-80 % time 19.4ns typ, 44.1ns min, 10.8ns max; typ from 0 V to 2.17 V
|   falling waveform, R_fixture 50.0, V_fixture 0V: 20-80 % time 416ps typ, 601ps min, 330ps max; typ from 2.17 V to 0 V
[POWER Clamp]
-3.3V     4.11A      4.173A     4.072A
-1.09V    352.5mA    415.9mA    314.5mA
-1.05V    284.5mA    347.9mA    246.5mA
-1.01V    216.5mA    279.9mA    178.5mA
-920mV    63.51mA    126.9mA    25.85mA
-900mV    31.51mA    92.9mA     9.552mA
-890mV    21.35mA    75.9mA     5.807mA
-870mV    9.804mA    44.01mA    2.146mA
-840mV    3.05mA     18.36mA    482.1uA
-780mV    295.2uA    3.194mA    24.34uA
-660mV    2.764uA    96.54uA    62.42nA
6.6V      0A         0A         0A
[GND Clamp]
-3.3V     -4.149A    -4.223A    -4.103A
-1.06V    -340.6mA   -415.4mA   -294.6mA
-940mV    -136.6mA   -211.4mA   -90.55mA
-910mV    -85.56mA   -160.4mA   -39.55mA
-900mV    -68.56mA   -143.4mA   -26.56mA
-880mV    -36.74mA   -109.4mA   -13.48mA
-860mV    -19.55mA   -75.41mA   -8.247mA
-840mV    -11.31mA   -44.9mA    -5.968mA
-810mV    -6.021mA   -21.14mA   -4.415mA
-700mV    -1.968mA   -2.918mA   -1.891mA
-470mV    -106.7uA   -266.5uA   -47.83uA
6.6V      9.456nA    1.185uA    63.86pA
| variable   typ   min   max
[Pullup Reference] 3.3V 2.7V 3.6V
| variable   typ   min   max
[Pulldown Reference] 0V 0V 0V
[Pullup]
-3.3V     28.29mA    15.58mA    40.83mA
-630mV    28.29mA    15.58mA    40.41mA
-480mV    25.11mA    15.58mA    33.22mA
-350mV    18.69mA    12.64mA    24.51mA
240mV     -11.89mA   -7.822mA   -15.87mA
710mV     -30.8mA    -19.68mA   -41.36mA
1.3V      -47.02mA   -28.56mA   -63.9mA
1.65V     -53.05mA   -30.92mA   -72.82mA
2.01V     -56.71mA   -31.98mA   -78.86mA
2.7V      -59.67mA   -33.14mA   -83.8mA
3.9V      -62.11mA   -34.07mA   -87.29mA
6.6V      -62.54mA   -34.07mA   -88.51mA
[Pulldown]
-3.3V     -40.25mA   -25.94mA   -51.99mA
-870mV    -40.25mA   -25.94mA   -51.33mA
-700mV    -35.92mA   -24.51mA   -45.06mA
-470mV    -25.89mA   -17.87mA   -32.39mA
240mV     12.97mA    8.52mA     16.62mA
590mV     28.62mA    18.11mA    37.2mA
1.07V     43.85mA    26mA       58.31mA
1.54V     51.42mA    28.24mA    70.48mA
2.01V     52.82mA    28.63mA    73.27mA
4.01V     56.01mA    32.56mA    75.18mA
4.53V     58.9mA     32.56mA    81.88mA
6.6V      58.9mA     32.56mA    81.88mA
[Ramp]
dV/dt_r 1.29886V/19.42298ns 851.11558mV/44.08485ns 1.57728V/10.77404ns
dV/dt_f 1.3278V/18.10185ns 831.26919mV/35.42753ns 1.59819V/11.71496ns
R_load = 50.0
| Removed startup time: 0s 0s 0s  .
| Removed end time: 3.936ns.
[Rising Waveform]
R_fixture   = 50.0
V_fixture   = 3.3V
V_fixture_min = 2.7V
V_fixture_max = 3.6V
0s        1.087V     1.314V     936.3mV
980ps     1.087V     1.314V     1.006V
1.044ns   1.086V     1.314V     1.299V
1.204ns   1.086V     1.314V     3.055V
1.408ns   1.438V     1.314V     3.524V
1.572ns   2.804V     1.313V     3.578V
1.76ns    3.21V      1.309V     3.592V
2.08ns    3.289V     1.463V     3.596V
2.486ns   3.297V     2.611V     3.598V
3.94ns    3.299V     2.7V       3.599V
| Removed startup time: 0s 0s 0s  .
| Removed end time: 252.64ns.
[Falling Waveform]
R_fixture   = 50.0
V_fixture   = 3.3V
V_fixture_min = 2.7V
V_fixture_max = 3.6V
0s        3.3V       2.7V       3.6V
6.56ns    3.3V       2.7V       3.547V
11.52ns   3.181V     2.7V       2.888V
18ns      2.706V     2.665V     1.934V
23.04ns   2.301V     2.586V     1.384V
32.8ns    1.602V     2.345V     1.055V
46.44ns   1.241V     1.968V     975.8mV
62.92ns   1.147V     1.622V     949.3mV
84.6ns    1.108V     1.446V     940.1mV
252.7ns   1.087V     1.315V     936.3mV
| Removed startup time: 0s 0s 0s  .
| Removed end time: 245.68ns.
[Rising Waveform]
R_fixture   = 50.0
V_fixture   = 0V
V_fixture_min = 0V
V_fixture_max = 0V
0s        7.747nV    280.7nV    5.724nV
5.84ns    3.468mV    -134.5uV   138.7mV
11ns      168.1mV    3.352mV    886.2mV
20.56ns   828.8mV    67.38mV    2.209V
31.12ns   1.548V     246.7mV    2.545V
38.32ns   1.875V     399.2mV    2.595V
48.76ns   2.049V     633.8mV    2.618V
72.68ns   2.145V     1.08V      2.628V
93.44ns   2.159V     1.278V     2.629V
245.8ns   2.165V     1.419V     2.629V
| Removed startup time: 0s 0s 0s  .
| Removed end time: 4.554ns.
[Falling Waveform]
R_fixture   = 50.0
V_fixture   = 0V
V_fixture_min = 0V
V_fixture_max = 0V
0s        2.165V     1.419V     2.629V
960ps     2.166V     1.419V     2.557V
1.14ns    2.172V     1.419V     2.026V
1.36ns    2.021V     1.418V     872.4mV
1.514ns   1.635V     1.42V      351.9mV
1.722ns   903mV      1.426V     101.5mV
1.97ns    306.9mV    1.393V     28.24mV
2.274ns   63.47mV    1.013V     7.327mV
3.032ns   3.511mV    120.1mV    999.8uV
4.558ns   336.3uV    181.7uV    526.4uV
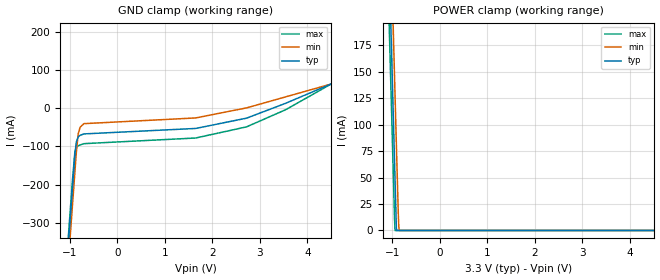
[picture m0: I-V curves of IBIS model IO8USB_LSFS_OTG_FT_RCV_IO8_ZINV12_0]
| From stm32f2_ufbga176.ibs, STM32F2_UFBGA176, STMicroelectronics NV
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| *** New cell (Generated with 5.14beta1 (Sep 20 2010 13:23:23))
[Model]   IO8USB_LSFS_OTG_FT_RCV_IO8_ZINV12_0
Model_type Input
Polarity   Non-Inverting
Enable   Active-Low
| CAP_THRESHOLD on pad DPV33 is "CMOS" :
| Rising=10.0% of vddio   Falling=90.0% of vddio
| C_comp min and max val. don't necessarily correlate with the min and max pvt
| but are the smallest and greatest pad capacitance found.
| var   typ   min   max
C_comp   1.91740pF  1.86162pF  1.98250pF
Vinl = 810.0mV | Dummy value overriden by next lines
Vinh = 2.52V | Dummy value overriden by next lines
[Model Spec]
| TIME_THRESHOLD on pin ZIPV12 is "CORE" :
| Rising=40.0% of vdd   Falling=60.0% of vdd
Vinl 1.25450V 1.03850V 1.36250V
Vinh 1.66150V 1.36950V 1.82450V
| variable   typ   min   max
[Temperature Range] 25.0 125.0 -40.0
| variable   typ   min   max
[Voltage Range] 3.3V 2.7V 3.6V
| variable   typ   min   max
[POWER Clamp Reference] 3.3V 2.7V 3.6V
| variable   typ   min   max
[GND Clamp Reference] 0V 0V 0V
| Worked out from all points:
|   POWER clamp passes 1 mA (typ) near -0.91 V on its own axis
[POWER Clamp]
-3.3V     3.936A     4.058A     3.841A
-1.13V    361.8mA    445mA      304.1mA
-1.09V    295.9mA    378.4mA    238.9mA
-1.05V    230mA      311.8mA    173.7mA
-1.01V    164.1mA    245.2mA    108.5mA
-950mV    65.28mA    145.3mA    10.76mA
-940mV    48.81mA    128.7mA    0A
-910mV    0A         78.72mA    0A
-870mV    0A         14.2mA     0A
-860mV    0A         3.389mA    0A
-850mV    0A         0A         0A
6.6V      0A         0A         0A
[GND Clamp]
-3.3V     -4.218A    -4.264A    -4.198A
-1.06V    -410mA     -456mA     -390.4mA
-940mV    -206mA     -252mA     -186.4mA
-890mV    -121mA     -167mA     -113.8mA
-860mV    -88.28mA   -116mA     -102.8mA
-820mV    -75.08mA   -66.92mA   -98.42mA
-780mV    -70.94mA   -49.85mA   -96.22mA
-700mV    -67.36mA   -40.52mA   -92.83mA
1.65V     -53.05mA   -25.58mA   -78.06mA
2.72V     -26.13mA   701.5uA    -48.88mA
3.54V     12.65mA    29.46mA    -4.159mA
6.6V      173.9mA    136.8mA    210.6mA
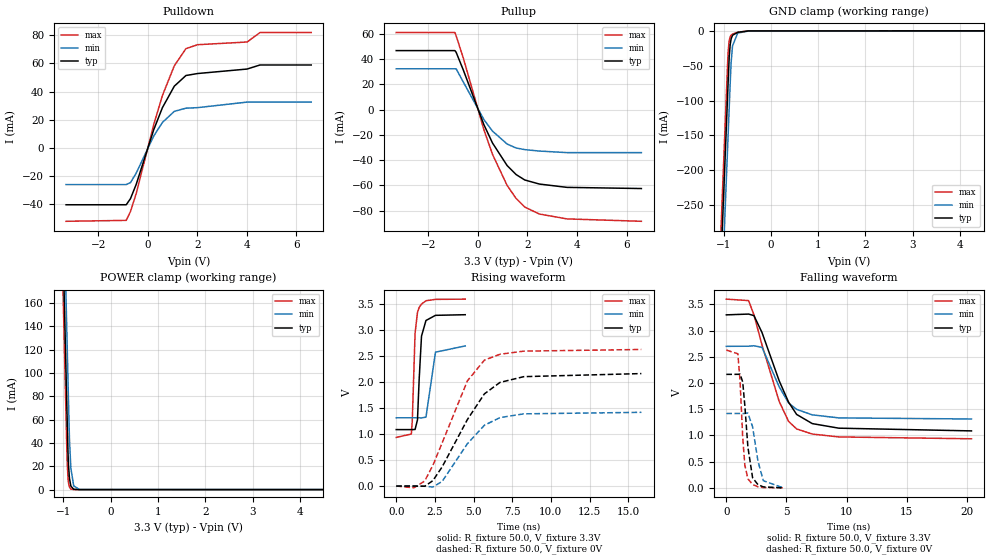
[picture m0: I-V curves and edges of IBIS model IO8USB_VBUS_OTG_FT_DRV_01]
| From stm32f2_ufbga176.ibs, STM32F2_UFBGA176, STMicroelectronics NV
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| *** New cell (Generated with 5.14beta1 (Sep 20 2010 13:23:23))
[Model]   IO8USB_VBUS_OTG_FT_DRV_01
Model_type 3-state
Polarity   Non-Inverting
Enable   Active-Low
| CAP_THRESHOLD on pad IOV33 is "CMOS" :
| Rising=10.0% of vddio   Falling=90.0% of vddio
| C_comp min and max val. don't necessarily correlate with the min and max pvt
| but are the smallest and greatest pad capacitance found.
| var   typ   min   max
C_comp   2.70355pF  2.58515pF  2.87895pF
Vmeas = 1.65V   | Reference voltage for timing measurements
Cref  = 50.0pF   | Timing specification test load capacitance value
Rref  = 10.0MOhm   | Timing specification test load resistance value
Vref  = 1.65V   | Timing specification test load voltage
[Model Spec]
| variable   typ   min   max
[Temperature Range] 25.0 125.0 -40.0
| variable   typ   min   max
[Voltage Range] 3.3V 2.7V 3.6V
| variable   typ   min   max
[POWER Clamp Reference] 3.3V 2.7V 3.6V
| variable   typ   min   max
[GND Clamp Reference] 0V 0V 0V
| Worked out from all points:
|   slope of the pulldown table from 0 to 0.495 V, typ, clamps not added: 20 ohm
|   slope of the pullup table from 0 to 0.495 V, typ, clamps not added: 21.7 ohm
|   GND clamp passes 1 mA (typ) near -0.61 V on its own axis
|   POWER clamp passes 1 mA (typ) near -0.81 V on its own axis
|   rising waveform, R_fixture 50.0, V_fixture 3.3V: 20-80 % time 203ps typ, 246ps min, 188ps max; typ from 1.09 V to 3.3 V
|   falling waveform, R_fixture 50.0, V_fixture 3.3V: 20-80 % time 2.3ns typ, 1.77ns min, 2.13ns max; typ from 3.3 V to 1.09 V
|   rising waveform, R_fixture 50.0, V_fixture 0V: 20-80 % time 2.49ns typ, 2.09ns min, 2.18ns max; typ from 0 V to 2.17 V
|   falling waveform, R_fixture 50.0, V_fixture 0V: 20-80 % time 463ps typ, 651ps min, 373ps max; typ from 2.17 V to 0.001 V
[POWER Clamp]
-3.3V     4.11A      4.173A     4.072A
-1.09V    352.5mA    415.9mA    314.5mA
-1.05V    284.5mA    347.9mA    246.5mA
-1.01V    216.5mA    279.9mA    178.5mA
-920mV    63.51mA    126.9mA    25.85mA
-900mV    31.51mA    92.9mA     9.552mA
-890mV    21.35mA    75.9mA     5.807mA
-870mV    9.804mA    44.01mA    2.146mA
-840mV    3.05mA     18.36mA    482.1uA
-780mV    295.2uA    3.193mA    24.34uA
-660mV    2.764uA    96.47uA    62.42nA
6.6V      0A         0A         0A
[GND Clamp]
-3.3V     -4.149A    -4.224A    -4.103A
-1.06V    -341.2mA   -416.1mA   -295.1mA
-940mV    -137.2mA   -212.1mA   -91.08mA
-910mV    -86.19mA   -161.1mA   -40.08mA
-900mV    -69.19mA   -144.1mA   -27.04mA
-880mV    -37.32mA   -110.1mA   -13.88mA
-860mV    -20.03mA   -76.14mA   -8.588mA
-840mV    -11.71mA   -45.57mA   -6.266mA
-810mV    -6.348mA   -21.68mA   -4.67mA
-700mV    -2.155mA   -3.174mA   -2.051mA
-470mV    -142.2uA   -334.3uA   -67.55uA
6.6V      13.96nA    1.746uA    94.44pA
| variable   typ   min   max
[Pullup Reference] 3.3V 2.7V 3.6V
| variable   typ   min   max
[Pulldown Reference] 0V 0V 0V
[Pullup]
-3.3V     46.81mA    32.38mA    61.09mA
-930mV    46.81mA    32.38mA    61.09mA
-880mV    45.47mA    32.38mA    58.55mA
-590mV    31.39mA    21.85mA    40.84mA
240mV     -11.89mA   -7.822mA   -15.87mA
590mV     -26.5mA    -17.07mA   -35.52mA
1.18V     -44.36mA   -27.27mA   -60.11mA
1.54V     -51.43mA   -30.39mA   -70.35mA
1.89V     -55.75mA   -31.69mA   -77.18mA
2.48V     -58.98mA   -32.83mA   -82.75mA
3.6V      -61.62mA   -34.07mA   -86.61mA
6.6V      -62.54mA   -34.07mA   -88.51mA
[Pulldown]
-3.3V     -40.26mA   -25.94mA   -51.99mA
-870mV    -40.25mA   -25.94mA   -51.33mA
-700mV    -35.92mA   -24.51mA   -45.06mA
-470mV    -25.89mA   -17.87mA   -32.39mA
240mV     12.97mA    8.52mA     16.62mA
590mV     28.62mA    18.11mA    37.2mA
1.07V     43.85mA    26mA       58.31mA
1.54V     51.42mA    28.24mA    70.48mA
2.01V     52.82mA    28.63mA    73.27mA
4.01V     56.01mA    32.56mA    75.18mA
4.53V     58.89mA    32.56mA    81.88mA
6.6V      58.89mA    32.56mA    81.88mA
[Ramp]
dV/dt_r 1.29886V/2.49261ns 851.30015mV/2.09022ns 1.57728V/2.18469ns
dV/dt_f 1.32782V/2.29911ns 831.60242mV/1.77435ns 1.59819V/2.13421ns
R_load = 50.0
| Removed startup time: 0s 0s 0s  .
| Removed end time: 4.459ns.
[Rising Waveform]
R_fixture   = 50.0
V_fixture   = 3.3V
V_fixture_min = 2.7V
V_fixture_max = 3.6V
0s        1.087V     1.314V     936.3mV
978ps     1.087V     1.314V     1.002V
1.039ns   1.086V     1.314V     1.254V
1.22ns    1.089V     1.314V     2.941V
1.375ns   1.274V     1.314V     3.341V
1.485ns   2.059V     1.314V     3.439V
1.636ns   2.886V     1.312V     3.503V
1.924ns   3.187V     1.326V     3.567V
2.539ns   3.286V     2.577V     3.593V
4.461ns   3.298V     2.697V     3.598V
| Removed startup time: 0s 0s 0s  .
| Removed end time: 20.37ns.
[Falling Waveform]
R_fixture   = 50.0
V_fixture   = 3.3V
V_fixture_min = 2.7V
V_fixture_max = 3.6V
0s        3.3V       2.7V       3.6V
1.85ns    3.315V     2.702V     3.572V
2.295ns   3.286V     2.711V     3.3V
2.965ns   2.963V     2.68V      2.726V
4.395ns   2.042V     1.927V     1.648V
5.18ns    1.633V     1.618V     1.267V
5.845ns   1.401V     1.497V     1.124V
7.145ns   1.226V     1.393V     1.027V
9.35ns    1.139V     1.335V     971.9mV
20.38ns   1.087V     1.314V     936.6mV
| Removed startup time: 0s 0s 0s  .
| Removed end time: 15.835ns.
[Rising Waveform]
R_fixture   = 50.0
V_fixture   = 0V
V_fixture_min = 0V
V_fixture_max = 0V
0s        10.14nV    410.7nV    7.088nV
1.135ns   -419.9uV   -6.583uV   -34.67mV
1.84ns    -4.024mV   -1.975mV   96.47mV
2.37ns    104.1mV    -19.52mV   397.7mV
2.97ns    368.8mV    89.45mV    831.3mV
4.6ns     1.279V     813.6mV    2.023V
5.7ns     1.774V     1.17V      2.424V
6.71ns    1.995V     1.318V     2.537V
8.255ns   2.106V     1.39V      2.597V
15.85ns   2.165V     1.419V     2.629V
| Removed startup time: 0s 0s 0s  .
| Removed end time: 4.711ns.
[Falling Waveform]
R_fixture   = 50.0
V_fixture   = 0V
V_fixture_min = 0V
V_fixture_max = 0V
0s        2.165V     1.419V     2.629V
958ps     2.166V     1.419V     2.558V
1.141ns   2.171V     1.419V     2.036V
1.362ns   2.019V     1.418V     964.1mV
1.542ns   1.56V      1.42V      427mV
1.794ns   775.1mV    1.426V     174.1mV
2.184ns   192.3mV    1.164V     66.01mV
2.629ns   62.63mV    509.9mV    20.57mV
3.076ns   19.15mV    136.8mV    5.99mV
4.713ns   1.175mV    2.615mV    716.5uV
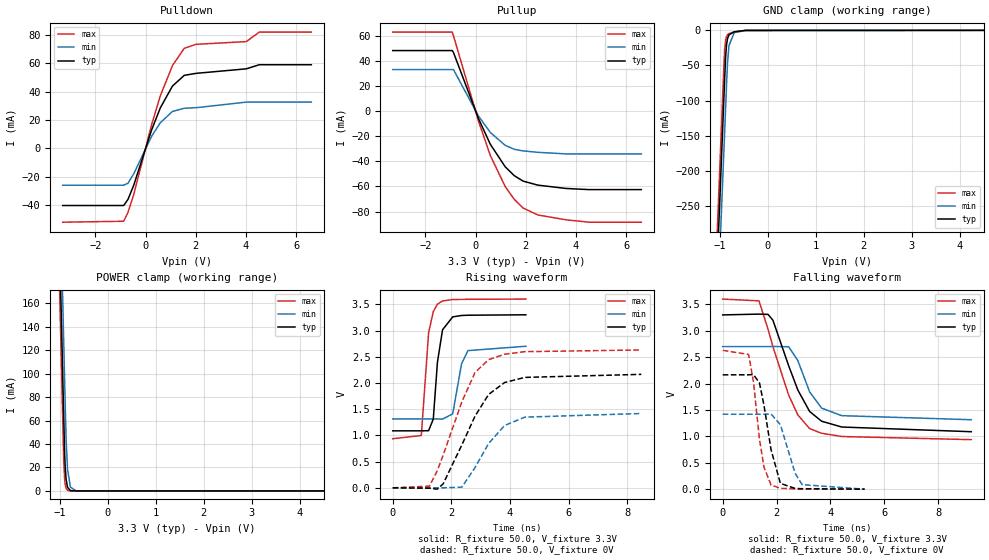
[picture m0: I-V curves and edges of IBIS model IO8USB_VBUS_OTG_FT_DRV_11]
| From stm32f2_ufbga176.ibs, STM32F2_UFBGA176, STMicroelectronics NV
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| *** New cell (Generated with 5.14beta1 (Sep 20 2010 13:23:23))
[Model]   IO8USB_VBUS_OTG_FT_DRV_11
Model_type 3-state
Polarity   Non-Inverting
Enable   Active-Low
| CAP_THRESHOLD on pad IOV33 is "CMOS" :
| Rising=10.0% of vddio   Falling=90.0% of vddio
| C_comp min and max val. don't necessarily correlate with the min and max pvt
| but are the smallest and greatest pad capacitance found.
| var   typ   min   max
C_comp   2.70355pF  2.58515pF  2.87895pF
Vmeas = 1.65V   | Reference voltage for timing measurements
Cref  = 50.0pF   | Timing specification test load capacitance value
Rref  = 10.0MOhm   | Timing specification test load resistance value
Vref  = 1.65V   | Timing specification test load voltage
[Model Spec]
| variable   typ   min   max
[Temperature Range] 25.0 125.0 -40.0
| variable   typ   min   max
[Voltage Range] 3.3V 2.7V 3.6V
| variable   typ   min   max
[POWER Clamp Reference] 3.3V 2.7V 3.6V
| variable   typ   min   max
[GND Clamp Reference] 0V 0V 0V
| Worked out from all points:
|   slope of the pulldown table from 0 to 0.495 V, typ, clamps not added: 20 ohm
|   slope of the pullup table from 0 to 0.495 V, typ, clamps not added: 21.7 ohm
|   GND clamp passes 1 mA (typ) near -0.61 V on its own axis
|   POWER clamp passes 1 mA (typ) near -0.81 V on its own axis
|   rising waveform, R_fixture 50.0, V_fixture 3.3V: 20-80 % time 205ps typ, 243ps min, 190ps max; typ from 1.09 V to 3.3 V
|   falling waveform, R_fixture 50.0, V_fixture 3.3V: 20-80 % time 1.04ns typ, 745ps min, 1.06ns max; typ from 3.3 V to 1.09 V
|   rising waveform, R_fixture 50.0, V_fixture 0V: 20-80 % time 1.14ns typ, 990ps min, 1.05ns max; typ from 0 V to 2.16 V
|   falling waveform, R_fixture 50.0, V_fixture 0V: 20-80 % time 433ps typ, 501ps min, 366ps max; typ from 2.17 V to 0 V
[POWER Clamp]
-3.3V     4.11A      4.173A     4.072A
-1.09V    352.5mA    415.9mA    314.5mA
-1.05V    284.5mA    347.9mA    246.5mA
-1.01V    216.5mA    279.9mA    178.5mA
-920mV    63.51mA    126.9mA    25.85mA
-900mV    31.51mA    92.9mA     9.552mA
-890mV    21.35mA    75.9mA     5.807mA
-870mV    9.804mA    44.01mA    2.146mA
-840mV    3.05mA     18.36mA    482.1uA
-780mV    295.2uA    3.193mA    24.34uA
-660mV    2.764uA    96.47uA    62.42nA
6.6V      0A         0A         0A
[GND Clamp]
-3.3V     -4.149A    -4.224A    -4.103A
-1.06V    -341.2mA   -416.1mA   -295.1mA
-940mV    -137.2mA   -212.1mA   -91.08mA
-910mV    -86.19mA   -161.1mA   -40.08mA
-900mV    -69.19mA   -144.1mA   -27.04mA
-880mV    -37.32mA   -110.1mA   -13.88mA
-860mV    -20.03mA   -76.14mA   -8.588mA
-840mV    -11.71mA   -45.57mA   -6.266mA
-810mV    -6.348mA   -21.68mA   -4.67mA
-700mV    -2.155mA   -3.174mA   -2.051mA
-470mV    -142.2uA   -334.3uA   -67.55uA
6.6V      13.96nA    1.746uA    94.44pA
| variable   typ   min   max
[Pullup Reference] 3.3V 2.7V 3.6V
| variable   typ   min   max
[Pulldown Reference] 0V 0V 0V
[Pullup]
-3.3V     48.28mA    33.1mA     63mA
-930mV    48.28mA    33.1mA     63mA
-880mV    46.73mA    33.1mA     60.07mA
120mV     -6.142mA   -4.065mA   -8.189mA
590mV     -26.5mA    -17.07mA   -35.52mA
1.18V     -44.36mA   -27.27mA   -60.11mA
1.54V     -51.43mA   -30.39mA   -70.35mA
1.89V     -55.75mA   -31.69mA   -77.18mA
2.48V     -58.98mA   -32.83mA   -82.75mA
3.6V      -61.62mA   -34.07mA   -86.61mA
4.51V     -62.54mA   -34.07mA   -88.51mA
6.6V      -62.54mA   -34.07mA   -88.51mA
[Pulldown]
-3.3V     -40.26mA   -25.94mA   -51.99mA
-870mV    -40.25mA   -25.94mA   -51.33mA
-700mV    -35.92mA   -24.51mA   -45.06mA
-470mV    -25.89mA   -17.87mA   -32.39mA
240mV     12.97mA    8.52mA     16.62mA
590mV     28.62mA    18.11mA    37.2mA
1.07V     43.85mA    26mA       58.31mA
1.54V     51.42mA    28.24mA    70.48mA
2.01V     52.82mA    28.63mA    73.27mA
4.01V     56.01mA    32.56mA    75.18mA
4.53V     58.89mA    32.56mA    81.88mA
6.6V      58.89mA    32.56mA    81.88mA
[Ramp]
dV/dt_r 1.29867V/1.14021ns 851.04862mV/989.5042ps 1.57718V/1.05226ns
dV/dt_f 1.32691V/1.03544ns 831.05752mV/744.61424ps 1.59728V/1.05735ns
R_load = 50.0
| Removed startup time: 0s 0s 0s  .
| Removed end time: 4.54ns.
[Rising Waveform]
R_fixture   = 50.0
V_fixture   = 3.3V
V_fixture_min = 2.7V
V_fixture_max = 3.6V
0s        1.087V     1.314V     936.3mV
976ps     1.087V     1.314V     997.6mV
1.225ns   1.09V      1.314V     2.96V
1.384ns   1.311V     1.314V     3.36V
1.526ns   2.396V     1.313V     3.503V
1.7ns     3.014V     1.311V     3.564V
2.047ns   3.26V      1.411V     3.591V
2.347ns   3.287V     2.362V     3.594V
2.567ns   3.292V     2.617V     3.595V
4.542ns   3.3V       2.7V       3.6V
| Removed startup time: 0s 0s 0s  .
| Removed end time: 9.227ns.
[Falling Waveform]
R_fixture   = 50.0
V_fixture   = 3.3V
V_fixture_min = 2.7V
V_fixture_max = 3.6V
0s        3.3V       2.7V       3.6V
1.346ns   3.315V     2.7V       3.566V
1.683ns   3.31V      2.7V       3.03V
1.864ns   3.199V     2.702V     2.697V
2.448ns   2.338V     2.697V     1.783V
2.788ns   1.879V     2.436V     1.406V
3.227ns   1.471V     1.843V     1.147V
3.671ns   1.287V     1.535V     1.059V
4.418ns   1.177V     1.392V     997.2mV
9.229ns   1.088V     1.315V     937.9mV
| Removed startup time: 0s 0s 0s  .
| Removed end time: 8.479ns.
[Rising Waveform]
R_fixture   = 50.0
V_fixture   = 0V
V_fixture_min = 0V
V_fixture_max = 0V
0s        10.12nV    410.7nV    7.11nV
1.252ns   -7.35mV    8.392uV    31.68mV
1.519ns   -25.64mV   109uV      323.6mV
1.721ns   75.71mV    132.6uV    624mV
2.358ns   816.9mV    13.07mV    1.639V
2.806ns   1.365V     384.8mV    2.197V
3.27ns    1.78V      844.4mV    2.444V
3.818ns   2.009V     1.19V      2.548V
4.507ns   2.106V     1.348V     2.597V
8.481ns   2.164V     1.418V     2.629V
| Removed startup time: 0s 0s 0s  .
| Removed end time: 5.264ns.
[Falling Waveform]
R_fixture   = 50.0
V_fixture   = 0V
V_fixture_min = 0V
V_fixture_max = 0V
0s        2.165V     1.419V     2.629V
963ps     2.166V     1.419V     2.551V
1.143ns   2.17V      1.419V     2.025V
1.365ns   2.012V     1.418V     941.7mV
1.534ns   1.584V     1.42V      416.3mV
1.794ns   749mV      1.424V     78.33mV
2.141ns   109.9mV    1.221V     16.65mV
2.687ns   14.29mV    302.7mV    5.459mV
2.951ns   8.457mV    85.34mV    3.74mV
5.266ns   156uV      209.5uV    129.1uV
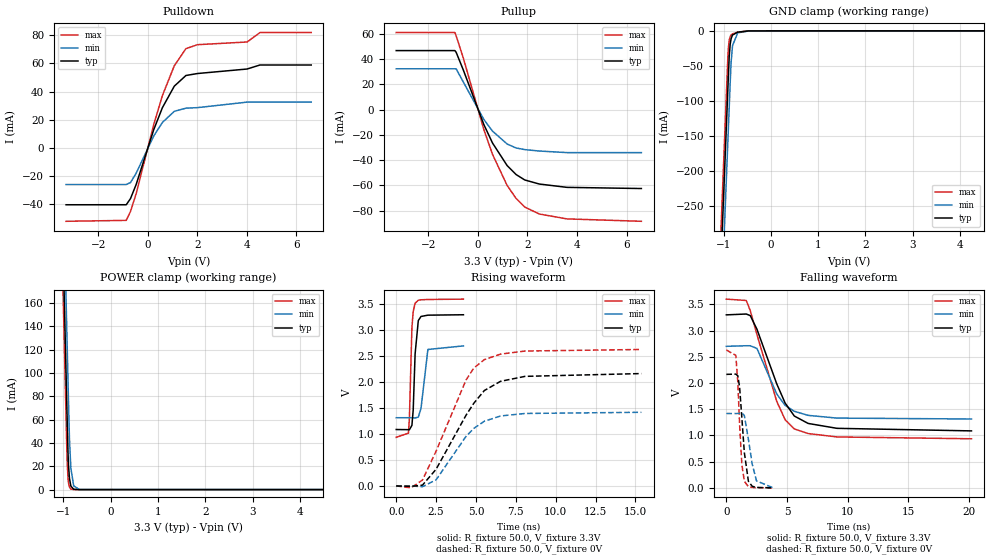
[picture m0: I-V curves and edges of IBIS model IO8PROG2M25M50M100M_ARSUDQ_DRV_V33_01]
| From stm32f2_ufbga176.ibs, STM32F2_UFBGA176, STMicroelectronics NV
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| *** New cell (Generated with 5.14beta1 (Sep 20 2010 13:23:23))
[Model]   IO8PROG2M25M50M100M_ARSUDQ_DRV_V33_01
Model_type 3-state
Polarity   Non-Inverting
Enable   Active-Low
| CAP_THRESHOLD on pad IOV33 is "CMOS" :
| Rising=10.0% of vddio   Falling=90.0% of vddio
| C_comp min and max val. don't necessarily correlate with the min and max pvt
| but are the smallest and greatest pad capacitance found.
| var   typ   min   max
C_comp   2.14295pF  2.03740pF  2.26750pF
Vmeas = 1.65V   | Reference voltage for timing measurements
Cref  = 50.0pF   | Timing specification test load capacitance value
Rref  = 1.0MOhm   | Timing specification test load resistance value
Vref  = 1.65V   | Timing specification test load voltage
[Model Spec]
| variable   typ   min   max
[Temperature Range] 25.0 125.0 -40.0
| variable   typ   min   max
[Voltage Range] 3.3V 2.7V 3.6V
| variable   typ   min   max
[POWER Clamp Reference] 3.3V 2.7V 3.6V
| variable   typ   min   max
[GND Clamp Reference] 0V 0V 0V
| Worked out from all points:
|   slope of the pulldown table from 0 to 0.495 V, typ, clamps not added: 20 ohm
|   slope of the pullup table from 0 to 0.495 V, typ, clamps not added: 21.7 ohm
|   GND clamp passes 1 mA (typ) near -0.62 V on its own axis
|   POWER clamp passes 1 mA (typ) near -0.81 V on its own axis
|   rising waveform, R_fixture 50.0, V_fixture 3.3V: 20-80 % time 162ps typ, 213ps min, 146ps max; typ from 1.09 V to 3.3 V
|   falling waveform, R_fixture 50.0, V_fixture 3.3V: 20-80 % time 2.26ns typ, 1.77ns min, 2.11ns max; typ from 3.3 V to 1.09 V
|   rising waveform, R_fixture 50.0, V_fixture 0V: 20-80 % time 2.49ns typ, 2.08ns min, 2.19ns max; typ from 0 V to 2.17 V
|   falling waveform, R_fixture 50.0, V_fixture 0V: 20-80 % time 416ps typ, 600ps min, 330ps max; typ from 2.17 V to 0.001 V
[POWER Clamp]
-3.3V     4.11A      4.173A     4.072A
-1.09V    352.5mA    415.9mA    314.5mA
-1.05V    284.5mA    347.9mA    246.5mA
-1.01V    216.5mA    279.9mA    178.5mA
-920mV    63.51mA    126.9mA    25.85mA
-900mV    31.51mA    92.9mA     9.552mA
-890mV    21.35mA    75.9mA     5.807mA
-870mV    9.804mA    44.01mA    2.146mA
-840mV    3.05mA     18.36mA    482.1uA
-780mV    295.2uA    3.194mA    24.34uA
-660mV    2.764uA    96.54uA    62.42nA
6.6V      0A         0A         0A
[GND Clamp]
-3.3V     -4.149A    -4.223A    -4.103A
-1.06V    -340.6mA   -415.4mA   -294.5mA
-940mV    -136.6mA   -211.4mA   -90.54mA
-910mV    -85.55mA   -160.4mA   -39.54mA
-900mV    -68.55mA   -143.4mA   -26.55mA
-880mV    -36.73mA   -109.4mA   -13.46mA
-860mV    -19.54mA   -75.4mA    -8.234mA
-840mV    -11.29mA   -44.89mA   -5.954mA
-810mV    -6.008mA   -21.13mA   -4.401mA
-700mV    -1.958mA   -2.906mA   -1.882mA
-470mV    -105.5uA   -263.9uA   -47.31uA
6.6V      9.456nA    1.185uA    63.86pA
| variable   typ   min   max
[Pullup Reference] 3.3V 2.7V 3.6V
| variable   typ   min   max
[Pulldown Reference] 0V 0V 0V
[Pullup]
-3.3V     46.78mA    32.36mA    61.06mA
-930mV    46.78mA    32.36mA    61.06mA
-880mV    45.45mA    32.36mA    58.53mA
-590mV    31.39mA    21.85mA    40.84mA
240mV     -11.89mA   -7.822mA   -15.87mA
590mV     -26.5mA    -17.07mA   -35.52mA
1.18V     -44.36mA   -27.27mA   -60.11mA
1.54V     -51.43mA   -30.39mA   -70.35mA
1.89V     -55.75mA   -31.69mA   -77.18mA
2.48V     -58.98mA   -32.83mA   -82.75mA
3.6V      -61.62mA   -34.07mA   -86.61mA
6.6V      -62.54mA   -34.07mA   -88.51mA
[Pulldown]
-3.3V     -40.26mA   -25.94mA   -51.99mA
-870mV    -40.25mA   -25.94mA   -51.33mA
-700mV    -35.92mA   -24.51mA   -45.06mA
-470mV    -25.89mA   -17.87mA   -32.39mA
240mV     12.97mA    8.52mA     16.62mA
590mV     28.62mA    18.11mA    37.2mA
1.07V     43.85mA    26mA       58.31mA
1.54V     51.42mA    28.24mA    70.48mA
2.01V     52.82mA    28.63mA    73.27mA
4.01V     56.01mA    32.54mA    75.18mA
4.53V     58.87mA    32.54mA    81.86mA
6.6V      58.87mA    32.54mA    81.86mA
[Ramp]
dV/dt_r 1.29886V/2.49099ns 851.30661mV/2.07522ns 1.57728V/2.18506ns
dV/dt_f 1.32782V/2.26503ns 831.60249mV/1.76768ns 1.59819V/2.10866ns
R_load = 50.0
| Removed startup time: 0s 0s 0s  .
| Removed end time: 4.212ns.
[Rising Waveform]
R_fixture   = 50.0
V_fixture   = 3.3V
V_fixture_min = 2.7V
V_fixture_max = 3.6V
0s        1.087V     1.314V     936.3mV
769ps     1.084V     1.314V     1.018V
828ps     1.083V     1.314V     1.317V
985ps     1.167V     1.313V     3.048V
1.066ns   1.464V     1.313V     3.359V
1.185ns   2.544V     1.31V      3.52V
1.385ns   3.185V     1.326V     3.577V
1.554ns   3.265V     1.491V     3.586V
1.986ns   3.29V      2.629V     3.592V
4.214ns   3.298V     2.698V     3.599V
| Removed startup time: 0s 0s 0s  .
| Removed end time: 20.18ns.
[Falling Waveform]
R_fixture   = 50.0
V_fixture   = 3.3V
V_fixture_min = 2.7V
V_fixture_max = 3.6V
0s        3.3V       2.7V       3.6V
1.64ns    3.316V     2.711V     3.574V
1.97ns    3.286V     2.711V     3.382V
2.52ns    3.027V     2.66V      2.925V
4.15ns    1.985V     1.792V     1.651V
4.845ns   1.617V     1.573V     1.299V
5.6ns     1.37V      1.461V     1.124V
6.74ns    1.229V     1.383V     1.036V
9.11ns    1.136V     1.331V     971.8mV
20.19ns   1.087V     1.314V     936.6mV
| Removed startup time: 0s 0s 0s  .
| Removed end time: 15.36ns.
[Rising Waveform]
R_fixture   = 50.0
V_fixture   = 0V
V_fixture_min = 0V
V_fixture_max = 0V
0s        7.751nV    280.7nV    5.706nV
925ps     -7.949mV   82.17uV    -37.07mV
1.645ns   14.76mV    -15.15mV   113.5mV
2.5ns     321.1mV    117.9mV    669.2mV
4.375ns   1.361V     954mV      2.039V
4.865ns   1.593V     1.108V     2.272V
5.525ns   1.838V     1.247V     2.433V
6.545ns   2.016V     1.348V     2.54V
8.08ns    2.111V     1.396V     2.599V
15.37ns   2.165V     1.419V     2.629V
| Removed startup time: 0s 0s 0s  .
| Removed end time: 3.856ns.
[Falling Waveform]
R_fixture   = 50.0
V_fixture   = 0V
V_fixture_min = 0V
V_fixture_max = 0V
0s        2.165V     1.419V     2.629V
781ps     2.17V      1.418V     2.528V
945ps     2.138V     1.419V     2.018V
1.095ns   1.919V     1.421V     1.196V
1.281ns   1.327V     1.427V     438.8mV
1.484ns   671.5mV    1.379V     125.5mV
1.818ns   126.7mV    925.3mV    24.07mV
2.132ns   30.31mV    453mV      8.772mV
2.485ns   8.72mV     133.8mV    3.651mV
3.858ns   694.4uV    844.8uV    552.2uV
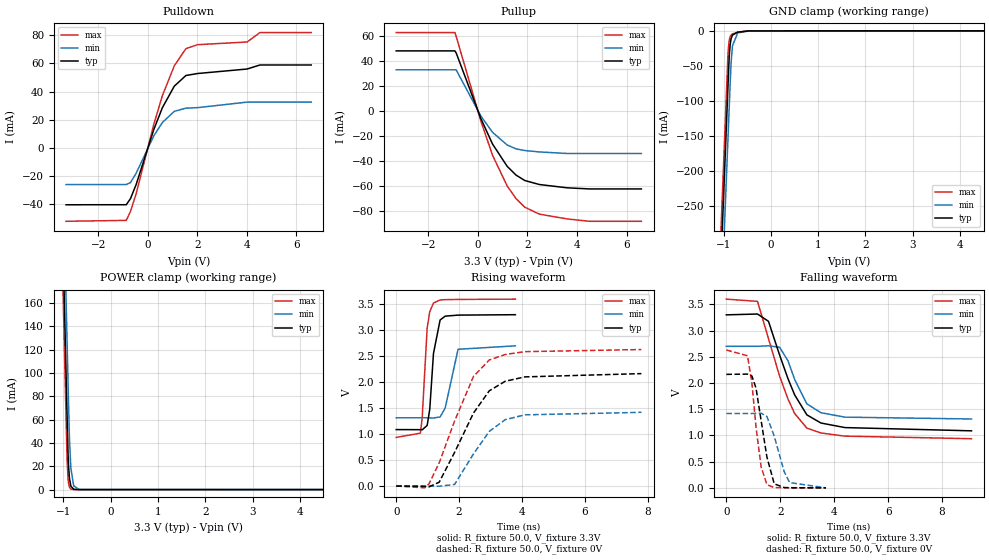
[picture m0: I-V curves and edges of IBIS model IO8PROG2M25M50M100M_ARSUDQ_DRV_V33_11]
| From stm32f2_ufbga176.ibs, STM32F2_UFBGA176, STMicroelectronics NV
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| *** New cell (Generated with 5.14beta1 (Sep 20 2010 13:23:23))
[Model]   IO8PROG2M25M50M100M_ARSUDQ_DRV_V33_11
Model_type 3-state
Polarity   Non-Inverting
Enable   Active-Low
| CAP_THRESHOLD on pad IOV33 is "CMOS" :
| Rising=10.0% of vddio   Falling=90.0% of vddio
| C_comp min and max val. don't necessarily correlate with the min and max pvt
| but are the smallest and greatest pad capacitance found.
| var   typ   min   max
C_comp   2.14295pF  2.03740pF  2.26750pF
Vmeas = 1.65V   | Reference voltage for timing measurements
Cref  = 50.0pF   | Timing specification test load capacitance value
Rref  = 1.0MOhm   | Timing specification test load resistance value
Vref  = 1.65V   | Timing specification test load voltage
[Model Spec]
| variable   typ   min   max
[Temperature Range] 25.0 125.0 -40.0
| variable   typ   min   max
[Voltage Range] 3.3V 2.7V 3.6V
| variable   typ   min   max
[POWER Clamp Reference] 3.3V 2.7V 3.6V
| variable   typ   min   max
[GND Clamp Reference] 0V 0V 0V
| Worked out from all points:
|   slope of the pulldown table from 0 to 0.495 V, typ, clamps not added: 20 ohm
|   slope of the pullup table from 0 to 0.495 V, typ, clamps not added: 21.7 ohm
|   GND clamp passes 1 mA (typ) near -0.62 V on its own axis
|   POWER clamp passes 1 mA (typ) near -0.81 V on its own axis
|   rising waveform, R_fixture 50.0, V_fixture 3.3V: 20-80 % time 164ps typ, 213ps min, 147ps max; typ from 1.09 V to 3.3 V
|   falling waveform, R_fixture 50.0, V_fixture 3.3V: 20-80 % time 1.01ns typ, 719ps min, 1.03ns max; typ from 3.3 V to 1.09 V
|   rising waveform, R_fixture 50.0, V_fixture 0V: 20-80 % time 1.11ns typ, 949ps min, 1.03ns max; typ from 0 V to 2.17 V
|   falling waveform, R_fixture 50.0, V_fixture 0V: 20-80 % time 398ps typ, 473ps min, 327ps max; typ from 2.17 V to 0 V
[POWER Clamp]
-3.3V     4.11A      4.173A     4.072A
-1.09V    352.5mA    415.9mA    314.5mA
-1.05V    284.5mA    347.9mA    246.5mA
-1.01V    216.5mA    279.9mA    178.5mA
-920mV    63.51mA    126.9mA    25.85mA
-900mV    31.51mA    92.9mA     9.552mA
-890mV    21.35mA    75.9mA     5.807mA
-870mV    9.804mA    44.01mA    2.146mA
-840mV    3.05mA     18.36mA    482.1uA
-780mV    295.2uA    3.194mA    24.34uA
-660mV    2.764uA    96.54uA    62.42nA
6.6V      0A         0A         0A
[GND Clamp]
-3.3V     -4.149A    -4.223A    -4.103A
-1.06V    -340.6mA   -415.4mA   -294.5mA
-940mV    -136.6mA   -211.4mA   -90.54mA
-910mV    -85.55mA   -160.4mA   -39.54mA
-900mV    -68.55mA   -143.4mA   -26.55mA
-880mV    -36.73mA   -109.4mA   -13.46mA
-860mV    -19.54mA   -75.4mA    -8.234mA
-840mV    -11.29mA   -44.89mA   -5.954mA
-810mV    -6.008mA   -21.13mA   -4.401mA
-700mV    -1.958mA   -2.906mA   -1.882mA
-470mV    -105.5uA   -263.9uA   -47.31uA
6.6V      9.456nA    1.185uA    63.86pA
| variable   typ   min   max
[Pullup Reference] 3.3V 2.7V 3.6V
| variable   typ   min   max
[Pulldown Reference] 0V 0V 0V
[Pullup]
-3.3V     48.26mA    33.09mA    62.98mA
-930mV    48.26mA    33.09mA    62.98mA
-880mV    46.71mA    33.09mA    60.06mA
120mV     -6.142mA   -4.065mA   -8.189mA
590mV     -26.5mA    -17.07mA   -35.52mA
1.18V     -44.36mA   -27.27mA   -60.11mA
1.54V     -51.43mA   -30.39mA   -70.35mA
1.89V     -55.75mA   -31.69mA   -77.18mA
2.48V     -58.98mA   -32.83mA   -82.75mA
3.6V      -61.62mA   -34.07mA   -86.61mA
4.51V     -62.54mA   -34.07mA   -88.51mA
6.6V      -62.54mA   -34.07mA   -88.51mA
[Pulldown]
-3.3V     -40.26mA   -25.94mA   -51.99mA
-870mV    -40.25mA   -25.94mA   -51.33mA
-700mV    -35.92mA   -24.51mA   -45.06mA
-470mV    -25.89mA   -17.87mA   -32.39mA
240mV     12.97mA    8.52mA     16.62mA
590mV     28.62mA    18.11mA    37.2mA
1.07V     43.85mA    26mA       58.31mA
1.54V     51.42mA    28.24mA    70.48mA
2.01V     52.82mA    28.63mA    73.27mA
4.01V     56.01mA    32.54mA    75.18mA
4.53V     58.87mA    32.54mA    81.86mA
6.6V      58.87mA    32.54mA    81.86mA
[Ramp]
dV/dt_r 1.29886V/1.11476ns 851.3068mV/948.61831ps 1.57728V/1.03494ns
dV/dt_f 1.32782V/1.00899ns 831.60271mV/720.39908ps 1.59819V/1.03426ns
R_load = 50.0
| Removed startup time: 0s 0s 0s  .
| Removed end time: 3.791ns.
[Rising Waveform]
R_fixture   = 50.0
V_fixture   = 3.3V
V_fixture_min = 2.7V
V_fixture_max = 3.6V
0s        1.087V     1.314V     936.3mV
769ps     1.085V     1.314V     1.018V
828ps     1.083V     1.314V     1.32V
985ps     1.166V     1.313V     3.044V
1.068ns   1.48V      1.313V     3.358V
1.186ns   2.552V     1.31V      3.525V
1.397ns   3.198V     1.33V      3.584V
1.559ns   3.272V     1.503V     3.59V
1.969ns   3.292V     2.634V     3.594V
3.793ns   3.3V       2.7V       3.6V
| Removed startup time: 0s 0s 0s  .
| Removed end time: 9.092ns.
[Falling Waveform]
R_fixture   = 50.0
V_fixture   = 3.3V
V_fixture_min = 2.7V
V_fixture_max = 3.6V
0s        3.3V       2.7V       3.6V
1.157ns   3.316V     2.7V       3.557V
1.563ns   3.177V     2.71V      2.848V
1.976ns   2.533V     2.681V     2.131V
2.284ns   2.087V     2.427V     1.699V
2.532ns   1.776V     2.072V     1.42V
2.988ns   1.392V     1.602V     1.14V
3.51ns    1.237V     1.433V     1.047V
4.399ns   1.15V      1.349V     986.9mV
9.094ns   1.088V     1.314V     937.7mV
| Removed startup time: 0s 0s 0s  .
| Removed end time: 7.801ns.
[Rising Waveform]
R_fixture   = 50.0
V_fixture   = 0V
V_fixture_min = 0V
V_fixture_max = 0V
0s        7.767nV    280.7nV    5.722nV
904ps     -7.209mV   64.8uV     -35.77mV
1.043ns   -16.98mV   186.3uV    39.84mV
1.368ns   73.48mV    -4.592mV   446.5mV
1.857ns   645.9mV    29.66mV    1.25V
2.46ns    1.406V     618.1mV    2.111V
2.962ns   1.834V     1.051V     2.427V
3.47ns    2.018V     1.278V     2.534V
4.094ns   2.102V     1.371V     2.588V
7.803ns   2.165V     1.419V     2.629V
| Removed startup time: 0s 0s 0s  .
| Removed end time: 3.695ns.
[Falling Waveform]
R_fixture   = 50.0
V_fixture   = 0V
V_fixture_min = 0V
V_fixture_max = 0V
0s        2.165V     1.419V     2.629V
785ps     2.17V      1.418V     2.52V
947ps     2.135V     1.419V     2.007V
1.101ns   1.904V     1.421V     1.159V
1.291ns   1.283V     1.425V     399.6mV
1.505ns   589mV      1.361V     61.55mV
1.777ns   76.78mV    986.6mV    6.09mV
2.147ns   6.264mV    307.2mV    2.045mV
2.348ns   3.338mV    100.9mV    1.629mV
3.697ns   392.7uV    311.5uV    358.1uV
